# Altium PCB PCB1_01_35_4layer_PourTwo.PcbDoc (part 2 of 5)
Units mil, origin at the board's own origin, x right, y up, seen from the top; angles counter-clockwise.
Board outline 1043.31 x 669.29 mil, 4 copper layers (Top Layer, Layer 1, Layer 2, Bottom Layer), stack 23.756 mil thick; 0 components, 1 nets, 8 pads, 85 vias.

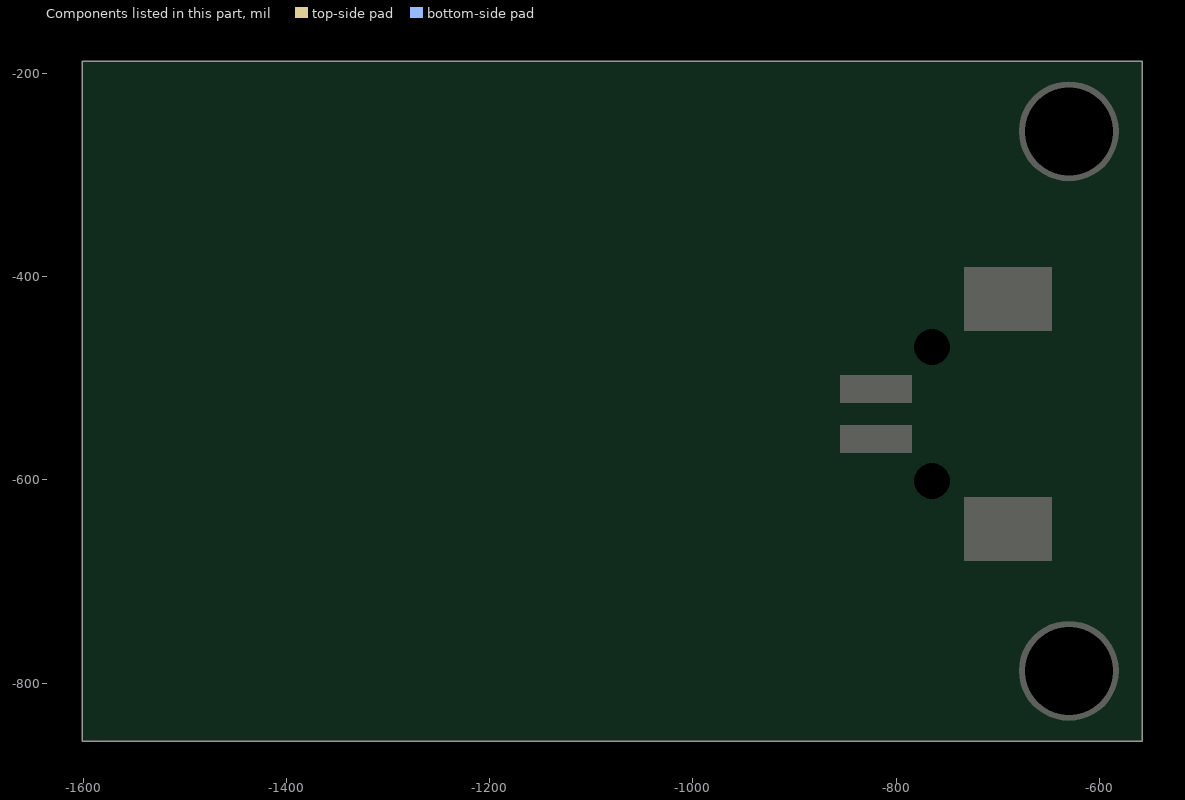
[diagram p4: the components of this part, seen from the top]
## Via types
v1: diameter 19.68, hole 11.81, Top Layer to Bottom Layer, tented both sides, 70 vias
v2: diameter 39.37, hole 19.68, Top Layer to Bottom Layer, 9 vias
v3: diameter 19.68, hole 11.81, Top Layer to Bottom Layer, 6 vias

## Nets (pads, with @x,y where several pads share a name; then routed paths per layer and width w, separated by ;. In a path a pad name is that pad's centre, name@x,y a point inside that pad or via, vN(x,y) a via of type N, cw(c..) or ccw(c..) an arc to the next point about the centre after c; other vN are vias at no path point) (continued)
copper on no net: | length 155578.5
  Top Layer w3.94: v3(-1265,-540) -1267.14,-537.86 -1277.26,-537.86 -1282.59,-532.53 -1296.93,-518.19 cw(c-1256.96,-523.28) -1294.61,-508.93 cw(c-1253.35,-524.64) -1290.23,-500.37 cw(c-1251.13,-526.07) -1284.09,-492.87 cw(c-1251.02,-526.13) -1276.51,-486.75 cw(c-1252.19,-524.27) -1267.78,-482.37 cw(c-1253.24,-521.43) -1258.21,-480.05 cw(c-1253.23,-522.64) -1248.3,-480.04 cw(c-1253.65,-526.46) -1238.57,-482.23 cw(c-1254.28,-528.41) -1229.43,-486.44 cw(c-1253.91,-527.86) -1221.33,-492.45 cw(c-1252.04,-525.86) -1214.69,-500.1 cw(c-1250.8,-524.81) -1207.42,-519.1 cw(c-1256.17,-525.78) -1207.1,-529.44 cw(c-1256.93,-525.82) -1212.86,-549.37 cw(c-1253.35,-527.65) -1218.84,-557.99 cw(c-1252.02,-528.72) -1226.74,-565.03 cw(c-1254.37,-525.34) -1236.08,-570.1 cw(c-1255.6,-522.41) -1246.37,-573.11 cw(c-1255.74,-521.9) -1257.1,-573.94 cw(c-1255.82,-524.09) -1267.8,-572.5 cw(c-1256.65,-527.38) -1277.97,-568.68 cw(c-1256.38,-527.19) -1287.01,-562.53 cw(c-1253.58,-523.93) -1294.51,-554.47 cw(c-1251.52,-522.34) -1300.19,-544.96 cw(c-1251.86,-522.45) -1303.81,-534.44 cw(c-1254.63,-523.07) -1305.1,-523.37 cw(c-1258.03,-523.09) -1303.83,-512.2 cw(c-1255.62,-523.78) -1299.96,-501.6 cw(c-1251.91,-525.6) -1293.83,-492.02 cw(c-1250.76,-526.42) -1276.23,-477.54 cw(c-1252.73,-522.76) -1265.48,-473.42 cw(c-1253.45,-520.19) -1253.97,-471.9 cw(c-1253.43,-524.34) -1242.38,-473.07 cw(c-1254.18,-528.01) -1231.22,-476.72 cw(c-1254.55,-528.93) -1221,-482.62 cw(c-1253.29,-527.26) -1212.22,-490.54 cw(c-1250.51,-524.79) -1205.38,-500.25 cw(c-1249.89,-524.29) -1200.98,-511.37 cw(c-1254.44,-525.51) -1199.18,-523.26 cw(c-1257.61,-525.68) -1199.94,-535.34 cw(c-1257.66,-525.72) -1203.17,-547.06 cw(c-1255.01,-526.79) -1208.82,-557.85 cw(c-1251.8,-528.95) -1216.81,-567.14 cw(c-1252.8,-527.63) -1226.81,-574.33 cw(c-1255.09,-523.58) -1238.21,-579.17 cw(c-1255.83,-521.27) -1250.45,-581.55 cw(c-1255.79,-522.21) -1262.96,-581.36 cw(c-1256.24,-525.69) -1275.15,-578.48 cw(c-1256.68,-527.57) -1296.14,-564.66 cw(c-1252.1,-522.82) -1303.91,-554.53 cw(c-1251.52,-522.32) -1312.48,-530.47 cw(c-1256.57,-523.09) -1312.7,-517.57 cw(c-1258.54,-523.01) -1309.87,-504.9 cw(c-1253.84,-524.66) -1304.21,-493.15 cw(c-1250.61,-526.63) -1296.13,-482.8 cw(c-1250.2,-526.96) -1286.06,-474.29 cw(c-1251.74,-524.63) -1274.4,-468.08 cw(c-1253.31,-520.68) -1261.59,-464.61 cw(c-1253.42,-521.25) -1248.25,-464.26 cw(c-1253.85,-526.37) -1235.1,-466.89 cw(c-1254.72,-529.28) -1222.71,-472.25 cw(c-1254.41,-528.82) -1211.66,-480.07 cw(c-1252.04,-526.16) -1202.51,-490.07 cw(c-1248.66,-523.69) -1195.85,-501.99 cw(c-1251.66,-524.79) -1192.14,-515.17 cw(c-1256.48,-525.61) -1191.39,-528.93 cw(c-1258.01,-525.64) -1198.42,-555.61 cw(c-1253.34,-527.91) -1206.05,-567.25 cw(c-1250.89,-529.85) -1216.26,-576.86 cw(c-1253.85,-525.8) -1228.44,-583.89 cw(c-1255.65,-521.78) -1241.92,-588.18 cw(c-1255.92,-520.74) -1256.07,-589.62 cw(c-1255.97,-523.38) -1270.21,-588.07 cw(c-1256.96,-527.83) -1283.72,-583.41 cw(c-1257.13,-528.59) -1295.82,-575.65 cw(c-1253.61,-524.27) -1305.91,-565.34 cw(c-1250.73,-521.95) -1313.66,-553.05 cw(c-1250.83,-521.94) -1318.73,-539.4 cw(c-1254.26,-522.78) -1320.8,-524.96 cw(c-1258.97,-522.93) -1319.54,-510.34 cw(c-1256.87,-523.55) -1314.87,-496.38 cw(c-1251.93,-525.83) -1307.2,-483.72 cw(c-1249.69,-527.47) -1297.02,-472.86 cw(c-1250.47,-526.49) -1284.79,-464.32 cw(c-1252.51,-522.73) -1270.99,-458.61 cw(c-1253.37,-520.73) -1241.1,-457.34 cw(c-1254.47,-528.4) -1226.56,-461.69 cw(c-1254.6,-529.11) -1201.58,-478.91 cw(c-1250.16,-524.75) -1192.42,-491.17 cw(c-1248.38,-523.54) -1186.35,-505.33 cw(c-1254,-525.2) -1183.64,-520.54 cw(c-1258.35,-525.54) -1184.22,-536.07 cw(c-1258.83,-525.53) -1187.99,-551.21 cw(c-1255.63,-526.74) -1194.86,-565.23 cw(c-1251.33,-529.48) -1204.75,-577.4 cw(c-1251.79,-528.69) -1217.27,-586.95 cw(c-1254.85,-523.58) -1231.67,-593.52 cw(c-1255.99,-520.32) -1247.21,-596.95 cw(c-1255.96,-521.1) -1263.16,-597.11 cw(c-1256.4,-525.38) -1278.79,-593.86 cw(c-1257.93,-530.08) -1293.35,-587.08 cw(c-1255.74,-526.81) -1305.95,-577.06 cw(c-1251.78,-522.79) -1316.14,-564.47 cw(c-1250.52,-521.81) -1327.8,-534.25 cw(c-1256.67,-522.9) -1328.53,-517.94 cw(c-1260.19,-522.75) -1325.42,-501.81 cw(c-1254.58,-524.57) -1318.67,-486.78 cw(c-1250.21,-527.09) -1308.82,-473.46 cw(c-1249.35,-527.8) -1296.4,-462.41 cw(c-1251.18,-525.17) -1281.93,-454.19 cw(c-1253.32,-520.19) -1265.94,-449.37 cw(c-1253.64,-519.61) -1249.18,-448.44 cw(c-1254.02,-526.02) -1232.59,-451.3 cw(c-1255.11,-530.05) -1216.87,-457.62 cw(c-1254.96,-529.88) -1202.75,-467.05 cw(c-1252.21,-526.65) -1190.95,-479.27 cw(c-1247.83,-523.27) -1182.18,-493.93 cw(c-1250.45,-524.22) -1177.07,-510.28 cw(c-1256.56,-525.42) -1175.67,-527.44 cw(c-1259.14,-525.47) -1183.57,-560.97 cw(c-1253.55,-528.02) -1192.67,-575.73 cw(c-1251.51,-529.18) -1219.91,-597.23 cw(c-1255.65,-521.33) -1236.52,-603.01 cw(c-1255.97,-520.77) -1271.66,-603.81 cw(c-1257.2,-528.02) -1288.56,-598.52 cw(c-1257.12,-528.46) -1303.87,-589.37 cw(c-1253.5,-523.69) -1316.82,-577.01 cw(c-1251.82,-522.11) -1333.64,-545.42 cw(c-1257.54,-523.82) -1336.56,-527.6 cw(c-1257.16,-524.04) -1335.3,-509.51 cw(c-1251.66,-525.02) -1330.08,-492.06 cw(c-1250.73,-525.22) -1309.27,-462.22 cw(c-1255.41,-520.37) -1294.43,-451.38 cw(c-1254.18,-522.94) -1277.46,-444.21 cw(c-1252.68,-527.83) -1259.25,-440.86 cw(c-1252.54,-528.84) -1240.68,-441.41 cw(c-1252.03,-525.45) -1222.63,-445.91 cw(c-1251.24,-522.58) -1191.66,-466.47 cw(c-1256.32,-527.92) -1180.21,-481.4 cw(c-1256.29,-527.98) -1172.11,-498.45 cw(c-1252.31,-526.64) -1167.87,-516.87 cw(c-1248.57,-526.1) -1167.93,-535.85 cw(c-1254.56,-525.38) -1172.26,-554.39 cw(c-1258.09,-524.2) -1180.47,-571.67 cw(c-1257.26,-524.78) -1192.15,-586.87 cw(c-1253.77,-528.17) -1206.88,-599.19 cw(c-1252.7,-529.4) -1224.11,-607.84 cw(c-1254.87,-523.56) -1242.9,-612.48 cw(c-1255.29,-521.49) -1281.46,-609.51 cw(c-1257.11,-527.94) -1299.39,-601.82 cw(c-1256.38,-527.17) -1315.14,-590.18 cw(c-1252.4,-522.83) -1328.01,-575.32 cw(c-1252.01,-522.31) -1343.14,-539.1 cw(c-1259.26,-523.81) -1344.4,-519.31 cw(c-1255.65,-524.18) -1341.1,-499.71 cw(c-1250.51,-525.6) -1333.61,-481.2 cw(c-1249.76,-525.92) -1322.38,-464.62 cw(c-1252.71,-523.36) -1307.84,-450.81 cw(c-1254.61,-521.4) -1271.24,-434.56 cw(c-1252.71,-528.95) -1251.04,-432.78 cw(c-1252.64,-528.68) -1230.87,-435.27 cw(c-1251.52,-524.1) -1211.69,-442.05 cw(c-1250.08,-520.82) -1194.49,-453.09 cw(c-1254.24,-525.9) -1180.16,-467.73 cw(c-1257.15,-528.28) -1169.21,-485.15 cw(c-1255.89,-527.74) -1162.15,-504.52 cw(c-1250.65,-526.48) -1159.47,-525 cw(c-1249.56,-526.22) -1161.58,-545.63 cw(c-1256.01,-524.84) -1168.21,-565.34 cw(c-1257.77,-524.21) -1193.12,-598.6 cw(c-1252.8,-529.75) -1210.44,-610.41 cw(c-1253.4,-528.05) -1230.06,-617.97 cw(c-1255,-522.12) -1250.94,-621.07 cw(c-1255.14,-520.4) -1272.08,-619.73 cw(c-1255.79,-523.81) -1292.47,-613.92 cw(c-1258.07,-529.4) -1311.1,-603.66 cw(c-1255.35,-525.87) -1326.95,-589.38 cw(c-1251.27,-522.17) -1339.4,-571.95 cw(c-1250.8,-521.82) -1347.94,-552.25 cw(c-1255.03,-523.08) -1352.08,-531.16 cw(c-1257.35,-523.68) -1345.7,-488.7 cw(c-1249.6,-526.23) -1335.72,-469.41 cw(c-1250.04,-525.84) -1321.88,-452.61 cw(c-1253.67,-522.07) -1304.71,-439.17 cw(c-1255.54,-519.38) -1284.86,-429.98 cw(c-1253.32,-526.08) -1263.39,-425.44 cw(c-1252.87,-529.81) -1241.36,-425.54 cw(c-1252.61,-528.08) -1219.82,-430.28 cw(c-1250.68,-522.48) -1199.79,-439.64 cw(c-1250.68,-521.94) -1182.38,-453.39 cw(c-1255.53,-526.88) -1168.39,-470.68 cw(c-1256.73,-527.88) -1152.66,-512.24 cw(c-1248.67,-526.53) -1151.94,-534.64 cw(c-1251.25,-526.05) -1156.39,-556.67 cw(c-1257.33,-524.15) -1165.55,-577.29 cw(c-1258.7,-523.45) -1178.87,-595.58 cw(c-1255.8,-526.15) -1195.79,-610.63 cw(c-1252.12,-531.33) -1215.73,-621.54 cw(c-1253.98,-526.36) -1237.68,-627.63 cw(c-1254.94,-520.79) -1260.51,-628.87 cw(c-1255,-520.48) -1283.15,-625.3 cw(c-1256.34,-525.23) -1304.52,-616.94 cw(c-1258.68,-529.88) -1323.5,-603.91 cw(c-1254.05,-524.62) -1339.1,-586.89 cw(c-1250.26,-521.75) -1350.76,-566.86 cw(c-1251.14,-522.06) -1357.97,-544.79 cw(c-1256.8,-523.21) -1360.24,-521.66 cw(c-1259.63,-523.39) -1357.13,-498.53 cw(c-1252.35,-525.21) -1348.94,-476.62 cw(c-1249.62,-526.41) -1319.69,-440.19 cw(c-1254.68,-520.35) -1299.82,-427.54 cw(c-1254.82,-520.74) -1277.52,-419.76 cw(c-1253.19,-527.75) -1253.97,-417.06 cw(c-1252.96,-528.94) -1207.64,-426.64 cw(c-1249.51,-520.74) -1187.1,-438.8 cw(c-1251.84,-523.38) -1169.86,-455.38 cw(c-1256.85,-527.63) -1156.57,-475.38 cw(c-1257.97,-528.31) -1147.74,-497.78 cw(c-1253.64,-527.18) -1143.87,-521.56 ; -1143.92,-649.83 ccw(c-1254.27,-527.48) -1119.72,-622.57 ccw(c-1259.21,-523.85) -1101.97,-590.77 ccw(c-1257.09,-524.63) -1091.4,-555.99 ccw(c-1247.91,-526.29) -1088.74,-519.81 ccw(c-1252.03,-526.77) -1094.28,-484.03 ccw(c-1258.09,-528.3) -1107.38,-450.31 ccw(c-1256.34,-527.26) -1127.31,-420.2 ccw(c-1249.3,-521.33) -1153.32,-395.25 ccw(c-1251.27,-524.44) -1184.21,-376.84 ccw(c-1254,-530.2) -1218.31,-365.53 ccw(c-1253.73,-528.4) -1253.98,-361.72 ccw(c-1253.83,-519.14) -1289.54,-365.83 ccw(c-1253.16,-519.96) -1323.12,-377.88 ccw(c-1249.17,-528.27) -1353.26,-396.93 ccw(c-1248.11,-529.79) -1378.72,-421.85 ccw(c-1253.51,-525.47) -1398.24,-451.52 ccw(c-1263.14,-520.54) -1410.57,-484.77 ccw(c-1255.65,-522.17) -1415,-519.87 ccw(c-1247.68,-522.38) -1411.79,-555.09 ccw(c-1247.71,-522.51) -1401.29,-588.81 ccw(c-1255.33,-525.91) -1383.87,-619.4 ccw(c-1262.38,-530.83) -1359.97,-645.2 ccw(c-1256.01,-523.32) -1330.95,-664.9 ccw(c-1252.86,-517.61) -1298.4,-677.98 ccw(c-1253.28,-519.52) -1263.91,-683.94 ccw(c-1253.81,-529.03) -1229.05,-682.28 ccw(c-1253.42,-533.71) -1195.54,-672.69 ccw(c-1258.72,-521.67) -1138.8,-633.11 ccw(c-1257.18,-522.66) -1117.99,-605.36 ccw(c-1248.17,-527.93) -1103.81,-573.79 ccw(c-1248.34,-528.35) -1097.28,-539.87 ccw(c-1260,-527.61) -1106.61,-471.92 ccw(c-1255.92,-525.9) -1121.73,-441.04 ccw(c-1246.77,-520.05) -1143.31,-414.35 ccw(c-1249.74,-523.56) -1170.34,-393.37 ccw(c-1254.28,-530.84) -1201.27,-378.74 ccw(c-1254.83,-532.06) -1234.54,-370.93 ccw(c-1254.06,-525.1) -1268.6,-370.38 ccw(c-1254.96,-515.06) -1301.86,-377.51 ccw(c-1252.24,-522.63) -1332.55,-391.97 ccw(c-1248.48,-528.93) -1359.43,-412.67 ccw(c-1248.92,-528.64) -1381.34,-438.49 ccw(c-1255.85,-524.03) -1397.13,-468.33 ccw(c-1262.74,-521.1) -1405.71,-500.93 ccw(c-1253.16,-522.45) -1406.74,-534.55 ccw(c-1247.28,-522.09) -1400.61,-567.61 ccw(c-1249.47,-522.86) -1387.72,-598.59 ccw(c-1257.67,-527.44) -1368.45,-625.94 ccw(c-1260.5,-529.45) -1343.46,-648.11 ccw(c-1253.62,-519.21) -1282.3,-673.69 ccw(c-1253.77,-521.58) -1249.16,-676.27 ccw(c-1253.4,-531.77) -1216.34,-671.51 ccw(c-1254.09,-530.79) -1185.57,-659.36 ccw(c-1258.25,-522.83) -1158.22,-640.8 ccw(c-1259.85,-520.78) -1135.39,-616.93 ccw(c-1255.33,-524.14) -1118.19,-588.85 ccw(c-1245.92,-528.54) -1107.71,-557.7 ccw(c-1251.18,-527.71) -1104.63,-525.07 ccw(c-1259.13,-527.77) -1108.68,-492.55 ccw(c-1259.98,-527.85) -1119.43,-461.65 ccw(c-1249.28,-522.09) -1159.32,-410.63 ccw(c-1251.38,-525.64) -1186.76,-393.25 ccw(c-1254.4,-531.62) -1217.27,-382.15 ccw(c-1254.29,-530.71) -1249.38,-377.68 ccw(c-1254.11,-522.44) -1281.58,-380.24 ccw(c-1255.08,-516.16) -1312.32,-390.06 ccw(c-1249.65,-527.35) -1363.58,-428.37 ccw(c-1250.18,-527.34) -1381.99,-454.67 ccw(c-1258.31,-522.95) -1394.18,-484.26 ccw(c-1260.39,-521.95) -1399.25,-515.81 ccw(c-1248.89,-522.27) -1388.57,-578.32 ccw(c-1251.45,-523.56) -1373.67,-606.4 ccw(c-1259.63,-529.17) -1352.98,-630.44 ccw(c-1258.48,-527.37) -1327.39,-649.04 ccw(c-1254.29,-520.12) -1298.39,-661.61 ccw(c-1253.57,-518.16) -1267.43,-667.81 ccw(c-1254,-523.9) -1235.95,-667.31 ccw(c-1252.75,-533.67) -1205.45,-659.78 ccw(c-1255.03,-528.22) -1177.55,-645.53 ccw(c-1259,-522.06) -1153.38,-625.61 ccw(c-1259.21,-521.7) -1133.94,-601.12 ccw(c-1248.9,-527.51) -1113.26,-542.8 ccw(c-1253.62,-527.47) -1113.3,-511.77 ccw(c-1259.69,-528.06) -1119.96,-481.47 ccw(c-1258.51,-527.55) -1132.79,-453.29 ccw(c-1251.51,-523.33) -1151.35,-428.63 ccw(c-1247.52,-519.94) -1175.01,-408.9 ccw(c-1253.73,-529.93) -1232.14,-387.18 ccw(c-1253.89,-528.93) -1262.76,-385.79 ccw(c-1254.52,-519.9) -1292.85,-391.13 ccw(c-1254.48,-518.67) -1320.86,-403.2 ccw(c-1249.03,-527.82) -1365.78,-443.79 ccw(c-1251.84,-526.07) -1380.78,-470.16 ccw(c-1260.64,-522.3) -1389.54,-499.13 ccw(c-1257.67,-522.5) -1391.42,-529.26 ccw(c-1249.9,-522.18) -1386.72,-559.05 ccw(c-1248.34,-521.87) -1375.89,-587.16 ccw(c-1253.48,-524.6) -1359.38,-612.25 ccw(c-1260.6,-530.49) -1337.71,-632.94 ccw(c-1256.93,-525.33) -1311.96,-648.12 ccw(c-1254.1,-519.22) -1283.57,-657.4 ccw(c-1254,-519.27) -1253.92,-660.53 ccw(c-1253.92,-526.31) -1224.39,-657.24 ccw(c-1252.42,-533.55) -1196.42,-647.35 ccw(c-1256.07,-526.19) -1171.47,-631.45 ccw(c-1259.45,-521.85) -1150.48,-610.61 ccw(c-1258.13,-522.79) -1134.36,-585.89 ccw(c-1250.93,-526.38) -1124.01,-558.36 ccw(c-1247.01,-527.68) -1120.25,-529.24 ccw(c-1258.04,-527.77) -1131.95,-472.19 ccw(c-1256.79,-526.92) -1146.47,-446.86 ccw(c-1249.69,-521.69) -1166.14,-425.39 ccw(c-1249.31,-521.82) -1190.16,-409.05 ccw(c-1253.75,-530.56) -1245.72,-393.65 ccw(c-1253.72,-526.87) -1274.57,-395.05 ccw(c-1255.19,-517.81) -1302.33,-402.82 ccw(c-1253.53,-521.11) -1327.5,-416.69 ccw(c-1249.44,-527.01) -1349.04,-435.67 ccw(c-1248.66,-527.86) -1366.11,-458.72 ccw(c-1253.76,-524.95) -1377.84,-484.77 ccw(c-1261.9,-522.29) -1383.38,-512.75 ccw(c-1255.3,-522.69) -1382.43,-541.17 ccw(c-1249.21,-521.89) -1375.41,-568.71 ccw(c-1249.55,-522.12) -1362.81,-594.12 ccw(c-1255.39,-525.93) -1345.1,-616.16 ccw(c-1260.04,-530.36) -1322.88,-633.55 ccw(c-1255.87,-523.52) -1297.39,-645.47 ccw(c-1254.2,-518.88) -1269.97,-651.71 ccw(c-1254.33,-520.79) -1241.91,-652.05 ccw(c-1253.52,-528.62) -1214.54,-646.31 ccw(c-1252.86,-531.63) -1189.27,-634.47 ccw(c-1258.42,-523) -1149.44,-596.01 ccw(c-1256.67,-523.88) -1136.52,-571.46 ccw(c-1248.7,-526.98) -1129.33,-544.74 ccw(c-1249.51,-527.21) -1128.48,-517.16 ccw(c-1256.94,-527.77) -1133.67,-490.09 ccw(c-1259.06,-528.32) -1144.42,-464.75 ccw(c-1255.01,-525.97) -1160.23,-442.33 ccw(c-1248.48,-520.18) -1180.61,-424.05 ccw(c-1250.76,-523.8) -1204.54,-410.95 ccw(c-1253.32,-529.88) -1230.73,-403.33 ccw(c-1253.54,-530.58) -1257.88,-401.38 ccw(c-1254.43,-520.47) -1309.96,-415.06 ccw(c-1252.49,-523.06) -1332.24,-430.29 ccw(c-1248.92,-527.33) -1350.74,-449.92 ccw(c-1249.57,-526.96) -1364.69,-472.94 ccw(c-1255.82,-524.1) -1373.32,-498.33 ccw(c-1261.08,-522.75) -1375.92,-524.97 ccw(c-1253.38,-522.61) -1372.5,-551.44 ccw(c-1249.1,-521.66) -1363.56,-576.58 ccw(c-1251.01,-522.68) -1349.57,-599.21 ccw(c-1257.04,-527.44) -1331.05,-618.19 ccw(c-1258.59,-528.83) -1308.72,-632.38 ccw(c-1254.61,-520.23) -1257.71,-644.71 ccw(c-1254.46,-522.58) -1231.5,-642.58 ccw(c-1252.86,-530.67) -1206.48,-634.73 ccw(c-1253.78,-529.37) -1183.99,-621.39 ccw(c-1257.9,-523.84) -1164.98,-603.49 ccw(c-1259.16,-522.65) -1150.17,-582.03 ccw(c-1254.95,-524.85) -1140.28,-558 ccw(c-1247.06,-527.11) -1136.03,-532.43 ccw(c-1251.79,-527.07) -1137.72,-506.64 ccw(c-1257.73,-528.07) -1144.92,-481.85 ccw(c-1258.08,-528.12) -1157.13,-459.16 ccw(c-1250.29,-522.17) -1194.51,-424.51 ccw(c-1251.75,-525.57) -1217.98,-414.44 ccw(c-1253.28,-530.35) -1243.05,-409.62 ccw(c-1253.28,-529.3) -1268.5,-410.15 ccw(c-1254.2,-522.62) -1293.16,-416.15 ccw(c-1255.52,-518.37) -1315.74,-427.6 ccw(c-1250.04,-526.23) -1350.67,-463.63 ccw(c-1250.83,-526.04) -1361.64,-486.27 ccw(c-1257.87,-523.57) -1367.39,-510.67 ccw(c-1258.95,-523.12) -1367.38,-535.68 ccw(c-1250.35,-521.99) -1351.37,-582.63 ccw(c-1252.56,-523.53) -1336.4,-602.45 ccw(c-1258.28,-528.98) -1317.45,-618.42 ccw(c-1257.26,-526.94) -1295.42,-629.58 ccw(c-1255.01,-521.03) -1271.52,-635.67 ccw(c-1254.74,-519.74) -1246.91,-636.62 ccw(c-1254.34,-524.49) -1222.76,-632.33 ccw(c-1252.2,-531.82) -1200.23,-622.76 ccw(c-1254.81,-527.52) -1180.55,-608.35 ccw(c-1258.47,-523.45) -1164.43,-590.07 ccw(c-1258.42,-523.38) -1152.53,-568.86 ccw(c-1249.59,-526.65) -1143.88,-521.56 ; -1143.92,-649.82 cw(c-1250.98,-530.7) -1173.69,-670.98 cw(c-1255.6,-522.46) -1207.45,-685.09 cw(c-1256.42,-520.13) -1243.5,-691.72 cw(c-1256.07,-526.12) -1280.17,-690.44 cw(c-1256.54,-531.16) -1315.68,-680.93 cw(c-1253.1,-522.25) -1348.28,-663.8 cw(c-1251.7,-519.95) -1376.56,-640.08 cw(c-1256,-523.94) -1399.09,-610.82 cw(c-1260.57,-527) -1414.5,-577.18 cw(c-1251.44,-523.96) -1422.13,-540.9 cw(c-1250.97,-523.53) -1413.63,-467.51 cw(c-1259.9,-521.06) -1397.43,-433.97 cw(c-1251.68,-526.2) -1374.19,-404.78 cw(c-1250.85,-526.51) -1311.81,-364.29 cw(c-1254.73,-517.71) -1275.41,-355.33 cw(c-1253.45,-527.36) -1237.86,-354.63 cw(c-1253.19,-528.51) -1166.45,-377.04 cw(c-1248.7,-519.64) -1136.14,-399.51 cw(c-1255.34,-526.77) -1111.52,-428.19 cw(c-1256.33,-527.88) -1083.09,-497.95 cw(c-1246.3,-525.66) -1081.07,-535.86 cw(c-1256.03,-525.08) -1087.51,-573.35 cw(c-1257.82,-524.93) -1123.37,-640.14 cw(c-1249.51,-531.46) -1151.47,-666.04 cw(c-1255.24,-523.6) -1184.67,-685.08 cw(c-1256.38,-521.83) -1259.48,-700.11 cw(c-1256.15,-532.66) -1297.58,-694.94 cw(c-1253.75,-523.3) -1333.64,-681.41 cw(c-1252.96,-521) -1393.27,-633.04 cw(c-1257.48,-525.8) -1426.34,-563.55 cw(c-1250.1,-523.24) -1427.08,-486.29 cw(c-1257.01,-522.7) -1394.41,-416.07 cw(c-1250.06,-526.97) -1334.98,-365.96 cw(c-1254.17,-520.97) -1259.59,-346.24 cw(c-1253.03,-529.4) -1182.62,-360.19 cw(c-1250.85,-522.11) -1118.99,-405.98 cw(c-1256.88,-528.57) -1080.44,-474.61 cw(c-1249.54,-525.55) -1075.13,-553.31 cw(c-1258.69,-524.96) -1103.62,-627.19 cw(c-1251.44,-528.92) -1161.22,-681.78 cw(c-1256.97,-521.21) -1236.77,-707.07 cw(c-1255.44,-533.1) -1276.91,-706.75 cw(c-1254.25,-524.75) -1316.02,-697.44 cw(c-1252.88,-520.17) -1384.07,-655.08 cw(c-1261.12,-528.95) -1409.56,-623.76 cw(c-1254.17,-524.73) -1427.42,-587.47 cw(c-1249.42,-522.76) -1438.21,-507.56 cw(c-1261.47,-521.99) -1430.29,-467.71 cw(c-1254.11,-524.57) -1413.62,-430.6 cw(c-1249.27,-527.16) -1358.59,-371.01 cw(c-1256.34,-517.37) -1322.63,-351.59 cw(c-1253.8,-524.37) -1283.17,-340.72 cw(c-1252.61,-530.98) -1242.21,-338.56 cw(c-1252.32,-528.04) -1201.69,-345.17 cw(c-1249.61,-518.44) -1163.58,-360.59 cw(c-1253.22,-524.51) -1129.86,-384.2 cw(c-1257.72,-529.82) -1101.93,-414.57 cw(c-1255.44,-528.3) -1081.08,-450.21 cw(c-1246.26,-524.25) -1068.58,-489.63 cw(c-1252.85,-525.24) -1065.26,-530.91 cw(c-1260.05,-525.15) -1070.9,-572.02 cw(c-1257.63,-525.88) -1085.16,-611.04 cw(c-1248.63,-530.4) -1107.69,-646 cw(c-1253.25,-526.2) -1137.55,-675.03 cw(c-1257.91,-520.4) -1173.04,-697.02 cw(c-1257.04,-522.54) -1212.42,-710.98 cw(c-1254.78,-532.37) -1253.96,-715.93 cw(c-1254.46,-526.59) -1295.6,-711.41 cw(c-1252.92,-519.06) -1335.39,-698 cw(c-1253.91,-520.9) -1371.45,-676.42 cw(c-1260.06,-528.89) -1401.92,-647.41 cw(c-1255.74,-525.77) -1425.12,-612.24 cw(c-1248.75,-522.06) -1440.23,-572.81 cw(c-1250.58,-522.41) -1446.62,-531.03 cw(c-1260.63,-522.76) -1443.68,-488.81 cw(c-1255.97,-524.03) -1431.29,-448.29 cw(c-1248.43,-527.15) -1410.42,-411.31 cw(c-1249.67,-526.09) -1382.13,-379.57 cw(c-1256.33,-518.6) -1347.54,-354.78 cw(c-1254.6,-522.56) -1308.2,-338.4 cw(c-1252.13,-530.59) -1266.16,-330.88 cw(c-1252.09,-529.19) -1223.43,-332.46 cw(c-1250.56,-519.34) -1182.05,-343.37 cw(c-1252.34,-522.69) -1144.14,-363.35 cw(c-1257.09,-529.91) -1111.36,-391.11 cw(c-1256.15,-529.21) -1085.2,-425.23 cw(c-1247.64,-524.14) -1067.12,-464.29 cw(c-1250.84,-524.73) -1058.3,-506.48 cw(c-1259.67,-525.69) -1058.81,-549.67 cw(c-1258.78,-525.94) -1068.49,-591.81 cw(c-1249.52,-529.25) -1087.16,-630.86 cw(c-1251.53,-527.43) -1114.19,-664.73 cw(c-1258.06,-521.07) -1147.98,-692.01 cw(c-1257.82,-521.72) -1186.84,-711.52 cw(c-1254.5,-530.88) -1229.06,-722.09 cw(c-1254.29,-528.74) -1272.64,-722.87 cw(c-1253.53,-519.42) -1315.43,-714.16 cw(c-1253.8,-519.79) -1355.46,-696.55 cw(c-1258.7,-528.1) -1390.71,-670.62 cw(c-1257.31,-527.33) -1419.24,-637.36 cw(c-1249.45,-521.84) -1439.92,-598.62 cw(c-1249.67,-521.77) -1451.92,-556.32 cw(c-1259.09,-523.27) -1454.43,-512.39 cw(c-1258.21,-523.83) -1446.95,-468.96 cw(c-1248.75,-526.45) -1430.18,-428.11 cw(c-1248.62,-526.36) -1405.1,-391.71 cw(c-1255.69,-520.13) -1372.67,-361.6 cw(c-1255.92,-520.67) -1334.24,-339.56 cw(c-1251.82,-529.85) -1291.84,-326.38 cw(c-1251.61,-530.15) -1247.56,-322.49 cw(c-1251.32,-520.84) -1203.46,-328.31 cw(c-1251.74,-520.42) -1161.75,-343.96 cw(c-1256.3,-529.64) -1124.37,-368.36 cw(c-1256.56,-530.19) -1092.97,-400.17 cw(c-1249.3,-524.56) -1069.22,-438.07 cw(c-1248.68,-523.71) -1054.6,-480.41 cw(c-1258.91,-526.11) -1049.56,-525 cw(c-1259.76,-526.26) -1054.09,-569.71 cw(c-1250.93,-528.25) -1068.22,-612.4 cw(c-1249.32,-528.44) -1091.65,-650.86 cw(c-1257.87,-521.96) -1122.97,-683.35 cw(c-1258.69,-521.2) -1160.52,-708.48 cw(c-1254.66,-529.15) -1202.64,-724.89 cw(c-1253.63,-531.12) -1247.45,-731.39 cw(c-1254.09,-520.18) -1292.68,-727.94 cw(c-1253.98,-518.8) -1336.2,-714.96 cw(c-1257.48,-526.85) -1375.91,-692.85 cw(c-1258.72,-529.39) -1409.67,-662.31 cw(c-1250.43,-521.94) -1435.98,-625.06 cw(c-1249.06,-521) -1453.8,-583.02 cw(c-1257.35,-523.39) -1462.13,-538.09 cw(c-1260.71,-524.09) -1460.11,-492.38 cw(c-1249.49,-525.76) -1448.11,-448.13 cw(c-1247.65,-526.32) -1426.96,-407.39 cw(c-1254.65,-521.53) -1397.49,-372.15 cw(c-1257.74,-518.93) -1360.79,-344.41 cw(c-1251.79,-528.8) -1318.83,-325.36 cw(c-1250.95,-530.83) -1273.71,-315.64 cw(c-1251.7,-522.54) -1227.54,-315.88 cw(c-1251.58,-517.91) -1182.54,-326.53 cw(c-1255.45,-528.94) -1140.9,-346.83 cw(c-1256.64,-531.11) -1104.46,-375.56 cw(c-1250.84,-525.37) -1075.06,-411.47 cw(c-1246.68,-522.2) -1054.47,-453.15 cw(c-1257.79,-526.3) -1043.52,-498.41 cw(c-1260.49,-526.81) -1042.43,-545.03 cw(c-1252.54,-527.6) -1051.41,-590.82 cw(c-1246.89,-528.99) -1070.49,-633.48 cw(c-1257.25,-522.96) -1098.53,-670.95 cw(c-1259.56,-521.01) -1133.95,-701.66 cw(c-1255.21,-527.51) -1175.16,-724.05 cw(c-1252.49,-533.28) -1220.42,-736.61 cw(c-1254.45,-521.35) -1267.41,-738.9 cw(c-1254.41,-518.04) -1313.89,-731.13 cw(c-1256.59,-525.36) -1357.63,-713.56 cw(c-1259.6,-531.63) -1396.36,-686.56 cw(c-1251.59,-522.44) -1428.24,-651.63 cw(c-1251.53,-521.79) -1466.41,-565.52 cw(c-1262.93,-524.86) -1470.32,-518.22 cw(c-1250.68,-525.19) -1463.69,-471.16 cw(c-1249.76,-524.93) -1421.44,-386.43 cw(c-1259.72,-517.8) -1387.33,-353.1 cw(c-1252.14,-527.48) -1346.63,-328.09 cw(c-1251.19,-528.38) -1253.95,-306.53 cw(c-1252.01,-515.75) -1206.28,-311.58 cw(c-1254.66,-527.78) -1160.84,-327.08 cw(c-1254.93,-529.44) -1084.77,-385.05 cw(c-1245.39,-520.52) -1058.14,-425.2 cw(c-1256.35,-526.13) -1041.03,-470.31 cw(c-1258.19,-527.07) -1037.21,-566.36 cw(c-1244.89,-528.84) -1051.22,-612.71 cw(c-1256.15,-523.98) -1075.21,-654.85 cw(c-1258.37,-522.91) -1147.14,-719.34 cw(c-1251.12,-534.6) -1192,-738.18 cw(c-1254.51,-522.9) -1240,-746.6 cw(c-1255.12,-520.09) -1336.02,-732.21 cw(c-1256.96,-528.26) -1416.62,-677.77 cw(c-1250.75,-520.9) -1466.96,-594.19 cw(c-1258.65,-524.78) -1476.45,-496.91 cw(c-1248.6,-524.93) -1443.97,-404.39 cw(c-1256.95,-521.04) -1374.73,-334.74 cw(c-1250.45,-529.25) -1282.28,-300.63 cw(c-1252.78,-519.91) -1184,-309.61 cw(c-1255.1,-530.55) -1098.38,-359.36 cw(c-1249.06,-522.54) -1042.38,-441.21 cw(c-1259.12,-527.66) -1026.07,-539.36 cw(c-1248.71,-527.29) -1053.56,-635.14 cw(c-1259.4,-522.6) -1119.12,-710.64 cw(c-1250.09,-534.56) -1162.7,-735.85 cw(c-1254.15,-524.75) -1210.88,-750.7 cw(c-1255.56,-519.13) -1311.32,-748.29 cw(c-1258.88,-533.98) -1358.76,-730.71 cw(c-1254.04,-524.95) -1401.11,-702.92 cw(c-1250.32,-519.96) -1463.56,-623.6 cw(c-1263.92,-526.85) -1480.34,-575.61 cw(c-1254.28,-524.94) -1485.95,-525.03 cw(c-1247.63,-524.64) -1464.53,-425.88 cw(c-1261.59,-518.54) -1438.13,-382.15 cw(c-1254.34,-524.5) -1402.56,-345.41 cw(c-1249.61,-529.78) -1312.08,-298.52 cw(c-1253.77,-515.16) -1261.32,-290.93 cw(c-1253.8,-524.07) -1210.1,-294.94 cw(c-1255.24,-532.49) -1160.84,-309.88 cw(c-1253.7,-529.28) -1115.85,-334.96 cw(c-1246.35,-519.04) -1077.47,-369.39 cw(c-1252.87,-524.35) -1047.77,-411.61 cw(c-1260.54,-528.74) -1027.8,-459.32 cw(c-1257.34,-527.96) -1018.41,-510.21 cw(c-1244.73,-527.11) -1020.47,-561.97 cw(c-1252.45,-525.51) -1034.14,-612 cw(c-1260.98,-522.3) -1058.28,-658.01 cw(c-1258.58,-524.11) -1091.67,-697.87 cw(c-1249.88,-533.3) -1133.06,-729.42 cw(c-1253.26,-526.81) -1180.53,-750.89 cw(c-1256.31,-517.9) -1231.61,-761.65 cw(c-1256.2,-520.64) -1283.85,-761.32 cw(c-1257.74,-533.18) -1334.78,-749.5 cw(c-1255.06,-527) -1381.8,-726.5 cw(c-1249.99,-518.73) -1422.84,-693.85 cw(c-1251.83,-520.35) -1456.03,-653.19 cw(c-1262.45,-527.14) -1479.5,-606.2 cw(c-1256.55,-525.5) -1491.8,-555.08 cw(c-1246.66,-524.1) -1492.8,-502.4 cw(c-1248.8,-523.74) -1482.58,-450.68 cw(c-1260.74,-519.9) -1461.24,-402.42 cw(c-1256.28,-523.1) -1429.55,-360.15 cw(c-1248.69,-530.03) -1389.41,-325.66 cw(c-1249.61,-528.39) -1342.82,-300.46 cw(c-1254.23,-516.8) -1291.81,-286.06 cw(c-1253.98,-521.63) -1238.8,-283.52 cw(c-1254.5,-532.18) -1186.4,-292.52 cw(c-1253.9,-530.71) -1137.06,-312.44 cw(c-1247.95,-519.85) -1093.25,-342.7 cw(c-1251.09,-522.6) -1057.34,-382.11 cw(c-1259.78,-529.09) -1030.75,-428.43 cw(c-1258.54,-528.73) -1014.59,-479.38 cw(c-1246.48,-526.42) -1009.95,-532.67 cw(c-1249.91,-525.75) -1017.46,-585.69 cw(c-1260.72,-523.12) -1036.29,-635.92 cw(c-1259.92,-523.71) -1065.39,-681.06 cw(c-1250.55,-531.46) -1103.65,-718.77 cw(c-1251.77,-528.94) -1149.5,-746.92 cw(c-1256.75,-518.68) -1200.44,-764.49 cw(c-1256.77,-519.37) -1254,-770.87 cw(c-1256.77,-531.4) -1307.7,-765.4 cw(c-1255.74,-529.57) -1358.83,-747.95 cw(c-1250.89,-518.94) -1405.05,-719.77 cw(c-1251.25,-519.12) -1444.27,-682.39 cw(c-1260.41,-526.69) -1474.43,-637.34 cw(c-1259,-526.66) -1493.67,-586.58 cw(c-1247.45,-523.56) -1501.44,-532.77 cw(c-1247.51,-523.38) -1497.62,-478.48 cw(c-1259.03,-521.17) -1482.06,-426.29 cw(c-1258.79,-521.96) -1455.1,-378.9 cw(c-1248.82,-529.04) -1418.42,-338.44 cw(c-1248.51,-529.11) -1373.95,-306.65 cw(c-1254.07,-518.96) -1323.61,-285.27 cw(c-1254.74,-518.93) -1269.67,-275.79 cw(c-1253.82,-531.4) -1214.88,-278.27 cw(c-1253.73,-532) -1161.8,-292.34 cw(c-1249.51,-521.39) -1113.02,-317.61 cw(c-1249.49,-520.24) -1071.15,-353.28 cw(c-1258.71,-529.07) -1038,-397.28 cw(c-1259.39,-529.69) -1014.91,-447.37 cw(c-1248.69,-526.23) -1003.23,-501.3 cw(c-1247.02,-525.45) -1004.02,-556.54 cw(c-1259.96,-523.94) -1016.85,-610.37 cw(c-1261.18,-523.7) -1040.85,-660.3 cw(c-1251.85,-529.66) -1075.1,-703.86 cw(c-1249.65,-530.98) -1118.35,-738.63 cw(c-1256.87,-519.83) -1168.22,-763.14 cw(c-1257.57,-518.44) -1222.23,-776.54 cw(c-1256.24,-529.24) -1277.87,-777.92 cw(c-1255.94,-532.53) -1332.46,-766.72 cw(c-1251.87,-519.64) -1383.36,-743.81 cw(c-1251.08,-517.93) -1428.3,-710.58 cw(c-1258.43,-525.7) -1464.99,-668.41 cw(c-1261.4,-528.44) -1491.28,-619 cw(c-1248.66,-523.27) -1506.13,-564.94 cw(c-1246.52,-522.74) -1509.17,-508.9 cw(c-1256.99,-522.03) -1500.04,-453.51 cw(c-1261.71,-521.27) -1478.63,-401.53 cw(c-1249.42,-527.9) -1446.3,-355.43 cw(c-1247.4,-529.43) -1404.87,-317.21 cw(c-1253.41,-521.07) -1356.16,-288.81 cw(c-1256.1,-516.26) -1302.24,-272.1 cw(c-1253.35,-530.15) -1245.88,-267.61 cw(c-1253.24,-533.02) -1189.78,-275.21 cw(c-1250.68,-523.26) -1136.62,-294.72 cw(c-1248.34,-517.48) -1089.16,-325.74 cw(c-1257.41,-528.59) -1049.62,-366.49 cw(c-1259.82,-530.7) -1019.59,-414.76 cw(c-1250.85,-526.55) -1000.66,-468.39 cw(c-1244.21,-524.54) -994.27,-524.97 cw(c-1258.7,-524.62) -1000.49,-581.65 cw(c-1262.2,-524.05) -1018.64,-635.78 cw(c-1253.49,-528.22) -1048.01,-684.76 cw(c-1247.16,-532.5) -1087.7,-725.93 cw(c-1256.55,-521.28) -1135.54,-757.39 cw(c-1258.48,-517.92) -1189.05,-778 cw(c-1256.21,-527.07) -1245.75,-786.62 cw(c-1255.48,-535.36) -1303.01,-782.27 cw(c-1252.79,-520.87) -1357.97,-765.39 cw(c-1251.29,-516.92) -1408.16,-737.17 cw(c-1256.76,-524.31) -1451.13,-698.81 cw(c-1263.2,-530.58) -1484.43,-651.73 cw(c-1250.24,-523.39) -1506.54,-598.4 cw(c-1249.66,-522.6) -1514.65,-483.7 cw(c-1264.43,-521.31) -1499.55,-427.8 cw(c-1250.58,-526.74) -1472.43,-376.55 cw(c-1249.21,-526.97) -1388.87,-296.86 cw(c-1257.86,-514.31) -1335.95,-272.76 cw(c-1253.22,-528.46) -1278.94,-260.94 cw(c-1252.5,-530.15) -1163.8,-274.6 cw(c-1248.05,-514.98) -1111.27,-300.11 cw(c-1256.01,-527.55) -1065.64,-336.65 cw(c-1257.2,-529.52) -1002.52,-434.49 cw(c-1242.25,-523.16) -988.62,-491.45 cw(c-1256.95,-525.03) -987.7,-550.15 cw(c-1259.71,-525.3) -1023.01,-661.61 cw(c-1244.96,-533.01) -1058.17,-708.82 cw(c-1255.68,-522.92) -1102.99,-747.1 cw(c-1257.92,-520.55) -1211.83,-791.11 cw(c-1254.8,-530.16) -1329.17,-783.96 cw(c-1252.94,-518.93) -1432.88,-727.91 cw(c-1258.75,-527.81) -1502.44,-632.56 cw(c-1248.42,-521.9) -1525.44,-516.45 cw(c-1259.48,-523.01) -1496.21,-401.6 cw(c-1247.9,-527.44) -1421.09,-309.5 cw(c-1256.06,-519.18) -1313.53,-258.61 cw(c-1252,-531.42) -1194.21,-257.79 cw(c-1250.66,-519.41) -1086,-308.42 cw(c-1257.82,-530.7) -1009.01,-400.22 cw(c-1247.25,-523.93) -978.91,-516.33 cw(c-1260.99,-525.61) -1000.67,-634.64 cw(c-1248.63,-529.68) -1071.22,-732.23 cw(c-1258.97,-519.81) -1176.68,-791.1 cw(c-1253.29,-537.3) -1236.53,-801.88 cw(c-1253.82,-524.91) -1297.32,-798.99 cw(c-1253.06,-517.69) -1410.35,-755.07 cw(c-1262.97,-533.22) -1457,-715.68 cw(c-1254.09,-525.27) -1493.66,-666.8 cw(c-1247.59,-521.01) -1532.01,-551.25 cw(c-1265.86,-523.24) -1531.4,-489.96 cw(c-1254.61,-524.99) -1517.05,-430.32 cw(c-1246.71,-527.47) -1452.19,-326.72 cw(c-1260.02,-514.83) -1404.4,-287.96 cw(c-1254.53,-524.15) -1349.08,-260.89 cw(c-1250.94,-533.58) -1289.14,-246.29 cw(c-1251.33,-529.19) -1227.44,-244.78 cw(c-1249.98,-514.08) -1166.87,-256.93 cw(c-1253.51,-523.66) -1110.53,-282.4 cw(c-1258.67,-532.73) -1060.89,-319.44 cw(c-1255.75,-529.88) -1020.23,-366.21 cw(c-1243.21,-521.28) -990.87,-420.83 cw(c-1252.26,-524.4) -974.51,-480.7 cw(c-1262.87,-526.26) -971.41,-542.8 cw(c-1259.15,-526.67) -981.57,-604.18 cw(c-1244.52,-530.86) -1005.02,-661.85 cw(c-1252.09,-526.16) -1040.87,-712.81 cw(c-1260.54,-518.94) -1086.93,-754.95 cw(c-1258.68,-521.81) -1140.91,-786.35 cw(c-1252.6,-535.74) -1200.52,-805.12 cw(c-1253.64,-527.6) -1262.88,-810.01 cw(c-1253.45,-516.15) -1324.94,-801.34 cw(c-1254.39,-519.07) -1383.77,-779.67 cw(c-1261.24,-532.59) -1436.44,-745.59 cw(c-1256.06,-527.19) -1480.13,-700.48 cw(c-1246.85,-519.83) -1513.12,-646.93 cw(c-1249.4,-520.82) -1534,-587.55 cw(c-1264.11,-524.14) -1541.35,-525 cw(c-1257.41,-524.72) -1534.42,-462.35 cw(c-1245.54,-527.2) -1514.09,-402.57 cw(c-1247.61,-526.01) -1481.53,-348.43 cw(c-1259.47,-516.84) -1437.86,-302.71 cw(c-1256.16,-521.79) -1384.96,-267.98 cw(c-1250.36,-532.81) -1325.72,-245.46 cw(c-1250.68,-530.8) -1263,-236.01 cw(c-1251.16,-515.93) -1199.7,-240.53 cw(c-1252.75,-520.84) -1138.99,-259.22 cw(c-1257.68,-532.64) -1083.66,-290.63 cw(c-1256.53,-531.4) -1036.23,-333.11 cw(c-1245.48,-521.65) -999.22,-384.95 cw(c-1249.56,-523.13) -974.82,-443.86 cw(c-1262.11,-526.94) -963.73,-506.76 cw(c-1260.78,-527.06) -966.24,-570.62 cw(c-1246.37,-529.34) -982.64,-632.42 cw(c-1249.33,-527.43) -1012.59,-688.98 cw(c-1260.52,-520.01) -1054.15,-737.8 cw(c-1260.02,-520.84) -1105.15,-776.71 cw(c-1252.68,-533.27) -1163.45,-803.58 cw(c-1252.81,-530.58) -1226.35,-816.61 cw(c-1254.26,-516.9) -1290.7,-815.69 cw(c-1254.54,-517.45) -1353.43,-801.13 cw(c-1259.38,-530.86) -1411.5,-773.25 cw(c-1257.84,-529.79) -1461.84,-732.93 cw(c-1247.99,-519.73) -1502.29,-682.58 cw(c-1248.29,-519.67) -1531.16,-624.74 cw(c-1261.53,-524.42) -1546.75,-561.99 cw(c-1260.6,-525.04) -1547.79,-497.27 cw(c-1246.26,-526.25) -1534.71,-433.77 cw(c-1246.04,-526.1) -1508.45,-374.44 cw(c-1257.97,-519.02) -1469.9,-322.22 cw(c-1258.51,-519.53) -1420.51,-280.01 cw(c-1250.13,-531.61) -1363.03,-249.5 cw(c-1249.73,-532.02) -1300.34,-231.87 cw(c-1251.84,-518.52) -1235.29,-228.26 cw(c-1252.53,-517.53) -1171.04,-239.44 cw(c-1256.58,-531.98) -1110.68,-264.38 cw(c-1256.83,-532.89) -1056.93,-301.6 cw(c-1247.9,-522.82) -1012.53,-349.59 cw(c-1246.85,-521.13) -980.06,-406.43 cw(c-1260.84,-527.34) -960.74,-469.07 cw(c-1262.07,-527.8) -955.14,-534.44 cw(c-1248.84,-528.25) -963.85,-599.49 cw(c-1246.01,-528.22) -987.02,-660.97 cw(c-1259.96,-521.26) -1023.11,-715.98 cw(c-1261.4,-520.36) -1070.09,-762.13 cw(c-1253.46,-530.68) -1125.96,-797.01 cw(c-1251.26,-533.66) -1188.33,-818.43 cw(c-1254.84,-518.19) -1253.96,-825.71 cw(c-1255.07,-516.13) -1319.71,-818.89 cw(c-1257.91,-528.59) -1382.43,-798.01 cw(c-1259.2,-532.99) -1438.9,-763.49 cw(c-1249.4,-520.16) -1486.51,-717.38 cw(c-1247.66,-518.42) -1523.29,-662.17 cw(c-1258.86,-524.07) -1547.27,-600.31 cw(c-1263.93,-526.08) -1556.71,-534.55 cw(c-1247.55,-525.45) -1551.51,-468.25 cw(c-1244.72,-525.76) -1532.33,-404.48 cw(c-1255.98,-520.81) -1499.84,-346.35 cw(c-1261.46,-517.66) -1455.04,-296.98 cw(c-1250.39,-530.05) -1400.43,-258.59 cw(c-1248.63,-532.77) -1338.84,-232.64 cw(c-1251.92,-521.18) -1273.11,-220.58 cw(c-1253.01,-514.09) -1206.27,-223.63 cw(c-1255.54,-530.72) -1141.65,-241.3 cw(c-1256.66,-534.18) -1082.19,-272.34 cw(c-1249.97,-524.47) -1030.8,-315.45 cw(c-1244.57,-518.56) -990.39,-369.08 cw(c-1259.16,-527.3) -962.73,-430.36 cw(c-1262.91,-528.76) -948.7,-496.2 cw(c-1251.43,-527.76) -949.16,-563.51 cw(c-1242.62,-528.28) -964.77,-629.07 cw(c-1258.79,-522.55) -994.47,-689.66 cw(c-1262.64,-520.37) -1036.41,-742.62 cw(c-1254.75,-528.39) -1088.76,-785.33 cw(c-1249.13,-536.21) -1149.44,-815.21 cw(c-1255.05,-519.98) -1215.29,-831 cw(c-1255.88,-515.23) -1283.07,-832.43 cw(c-1257.01,-526.14) -1349.59,-819.27 cw(c-1259.73,-536.19) -1411.51,-791.47 cw(c-1250.94,-521.2) -1465.84,-750.65 cw(c-1250.97,-520.21) -1542.67,-639.3 cw(c-1266.62,-527.73) -1560.8,-573.63 cw(c-1249.4,-524.95) -1563.99,-505.51 cw(c-1248.1,-524.35) -1527.02,-374.87 cw(c-1264.36,-516.75) -1487.86,-318.84 cw(c-1251.24,-528.27) -1437.22,-272.81 cw(c-1249.63,-529.36) -1312.54,-217.83 cw(c-1254.2,-511.43) -1244.16,-212.26 cw(c-1254.73,-528.86) -1176.18,-221.98 cw(c-1254.7,-531.35) -1053.92,-283.22 cw(c-1244.75,-517.49) -1005.84,-332.51 cw(c-1257.44,-527.46) -969.76,-391.26 v2@-914.51,-446.51
  Top Layer w27.56: v2(-856,-624) -835,-624 -819.92,-608.92 -819.92,-559.61 ; v2(-851,-440) -819.92,-471.08 -819.92,-510.39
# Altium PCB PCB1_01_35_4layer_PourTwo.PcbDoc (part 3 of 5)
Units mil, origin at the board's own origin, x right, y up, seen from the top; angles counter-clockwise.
Board outline 1043.31 x 669.29 mil, 4 copper layers (Top Layer, Layer 1, Layer 2, Bottom Layer), stack 23.756 mil thick; 0 components, 1 nets, 8 pads, 85 vias.

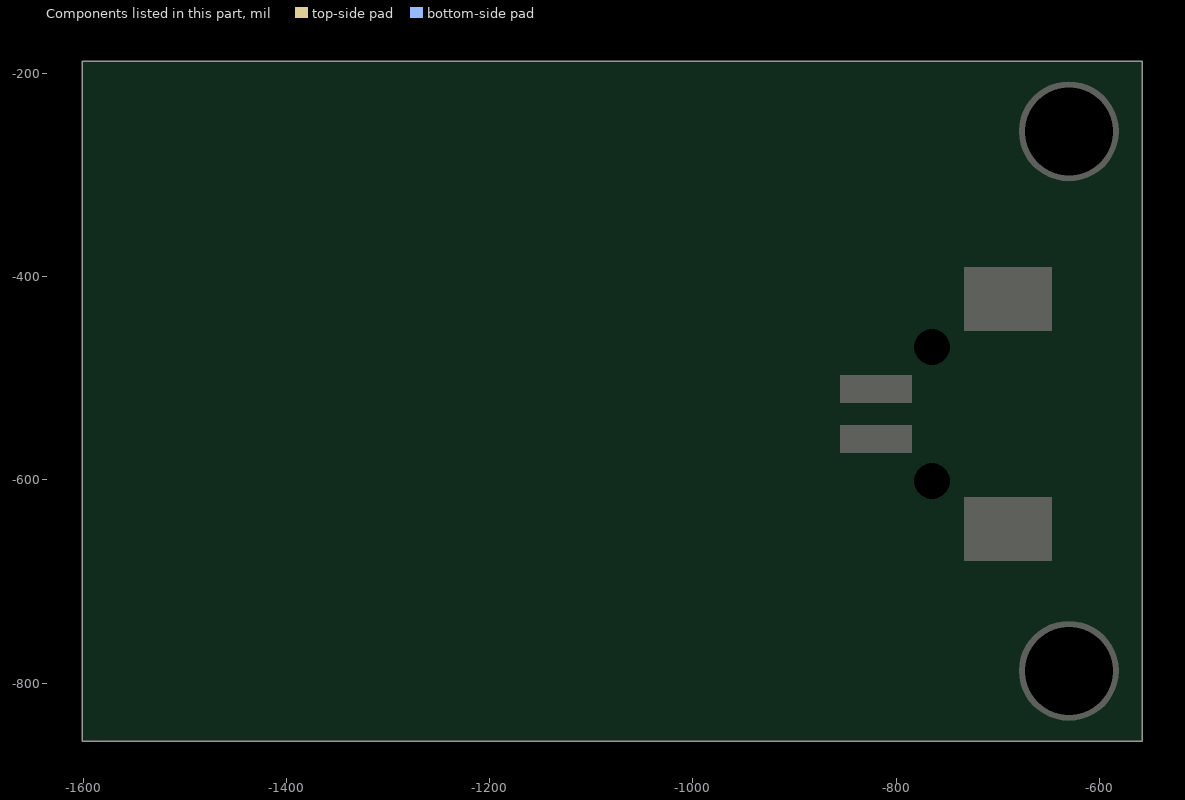
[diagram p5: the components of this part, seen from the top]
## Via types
v1: diameter 19.68, hole 11.81, Top Layer to Bottom Layer, tented both sides, 70 vias
v2: diameter 39.37, hole 19.68, Top Layer to Bottom Layer, 9 vias
v3: diameter 19.68, hole 11.81, Top Layer to Bottom Layer, 6 vias

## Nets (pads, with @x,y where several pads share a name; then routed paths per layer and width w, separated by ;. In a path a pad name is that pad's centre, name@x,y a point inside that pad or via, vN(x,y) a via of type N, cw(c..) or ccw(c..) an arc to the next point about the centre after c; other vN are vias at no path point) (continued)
copper on no net: (continued)
  Layer 2 w3.94: -1375.27,-569.03 ccw(c-1249.41,-522.43) -1362.67,-594.44 ccw(c-1255.25,-526.24) -1344.96,-616.47 ccw(c-1259.89,-530.67) -1322.74,-633.86 ccw(c-1255.73,-523.83) -1297.25,-645.79 ccw(c-1254.06,-519.19) -1269.82,-652.02 ccw(c-1254.19,-521.1) -1241.77,-652.37 ccw(c-1253.38,-528.94) -1214.4,-646.62 ccw(c-1252.72,-531.94) -1189.13,-634.78 ccw(c-1258.28,-523.31) -1149.3,-596.33 ccw(c-1256.53,-524.2) -1136.37,-571.78 ccw(c-1248.56,-527.29) -1129.19,-545.05 ccw(c-1249.37,-527.52) -1128.34,-517.47 ccw(c-1256.8,-528.08) -1133.53,-490.41 ccw(c-1258.92,-528.63) -1144.28,-465.06 ccw(c-1254.86,-526.29) -1160.09,-442.65 ccw(c-1248.34,-520.49) -1180.46,-424.36 ccw(c-1250.61,-524.11) -1204.4,-411.26 ccw(c-1253.18,-530.19) -1230.58,-403.65 ccw(c-1253.4,-530.89) -1257.74,-401.69 ccw(c-1254.29,-520.78) -1309.82,-415.37 ccw(c-1252.35,-523.37) -1332.1,-430.6 ccw(c-1248.78,-527.65) -1350.6,-450.23 ccw(c-1249.43,-527.27) -1364.54,-473.25 ccw(c-1255.68,-524.42) -1373.18,-498.64 ccw(c-1260.94,-523.06) -1375.78,-525.28 ccw(c-1253.24,-522.92) -1372.36,-551.76 ccw(c-1248.95,-521.97) -1363.41,-576.89 ccw(c-1250.87,-522.99) -1349.43,-599.52 ccw(c-1256.9,-527.75) -1330.91,-618.5 ccw(c-1258.45,-529.14) -1308.58,-632.69 ccw(c-1254.47,-520.55) -1257.56,-645.03 ccw(c-1254.32,-522.89) -1231.36,-642.89 ccw(c-1252.72,-530.99) -1206.33,-635.04 ccw(c-1253.64,-529.68) -1183.85,-621.7 ccw(c-1257.76,-524.16) -1164.84,-603.81 ccw(c-1259.02,-522.96) -1150.03,-582.34 ccw(c-1254.81,-525.16) -1140.13,-558.32 ccw(c-1246.92,-527.43) -1135.88,-532.74 ccw(c-1251.64,-527.38) -1137.57,-506.96 ccw(c-1257.59,-528.38) -1144.78,-482.16 ccw(c-1257.94,-528.43) -1156.99,-459.47 ccw(c-1250.14,-522.48) -1194.37,-424.82 ccw(c-1251.61,-525.89) -1217.84,-414.76 ccw(c-1253.14,-530.66) -1242.9,-409.93 ccw(c-1253.14,-529.61) -1268.36,-410.46 ccw(c-1254.06,-522.94) -1293.01,-416.46 ccw(c-1255.38,-518.68) -1315.59,-427.91 ccw(c-1249.89,-526.55) -1350.53,-463.95 ccw(c-1250.69,-526.35) -1361.5,-486.58 ccw(c-1257.73,-523.88) -1367.25,-510.98 ccw(c-1258.81,-523.44) -1367.23,-535.99 ccw(c-1250.2,-522.3) -1351.23,-582.94 ccw(c-1252.42,-523.84) -1336.25,-602.76 ccw(c-1258.14,-529.29) -1317.31,-618.73 ccw(c-1257.12,-527.25) -1295.28,-629.89 ccw(c-1254.86,-521.34) -1271.38,-635.99 ccw(c-1254.59,-520.05) -1246.77,-636.93 ccw(c-1254.2,-524.8) -1222.61,-632.65 ccw(c-1252.05,-532.14) -1200.09,-623.07 ccw(c-1254.67,-527.83) -1180.4,-608.66 ccw(c-1258.32,-523.76) -1164.29,-590.38 ccw(c-1258.27,-523.69) -1152.39,-569.17 ccw(c-1249.45,-526.97) -1143.73,-521.88 ccw(c-1253.5,-527.49) -1147.59,-498.09 ccw(c-1257.83,-528.62) -1156.43,-475.69 ccw(c-1256.71,-527.94) -1169.72,-455.7 ccw(c-1251.69,-523.7) -1186.96,-439.12 ccw(c-1249.37,-521.06) -1207.5,-426.95 ccw(c-1252.82,-529.26) -1253.83,-417.37 ccw(c-1253.05,-528.07) -1277.37,-420.07 ccw(c-1254.68,-521.05) -1299.68,-427.85 ccw(c-1254.53,-520.66) -1319.55,-440.5 ccw(c-1249.48,-526.73) -1348.8,-476.94 ccw(c-1252.21,-525.53) -1356.99,-498.85 ccw(c-1259.49,-523.71) -1360.1,-521.97 ccw(c-1256.66,-523.53) -1357.83,-545.11 ccw(c-1251,-522.38) -1350.61,-567.17 ccw(c-1250.11,-522.07) -1338.95,-587.2 ccw(c-1253.9,-524.93) -1323.36,-604.22 ccw(c-1258.54,-530.2) -1304.38,-617.26 ccw(c-1256.2,-525.54) -1283.01,-625.61 ccw(c-1254.86,-520.79) -1260.37,-629.19 ccw(c-1254.8,-521.11) -1237.53,-627.95 ccw(c-1253.84,-526.67) -1215.59,-621.85 ccw(c-1251.98,-531.64) -1195.65,-610.95 ccw(c-1255.66,-526.46) -1178.73,-595.89 ccw(c-1258.56,-523.76) -1165.41,-577.6 ccw(c-1257.19,-524.46) -1156.25,-556.99 ccw(c-1251.11,-526.36) -1151.8,-534.96 ccw(c-1248.53,-526.84) -1152.52,-512.55 ccw(c-1256.58,-528.19) -1168.25,-471 ccw(c-1255.38,-527.19) -1182.24,-453.7 ccw(c-1250.54,-522.26) -1199.64,-439.95 ccw(c-1250.54,-522.79) -1219.67,-430.59 ccw(c-1252.46,-528.39) -1241.22,-425.86 ccw(c-1252.73,-530.12) -1263.25,-425.75 ccw(c-1253.17,-526.39) -1284.71,-430.29 ccw(c-1255.4,-519.7) -1304.57,-439.48 ccw(c-1253.53,-522.38) -1321.74,-452.92 ccw(c-1249.9,-526.16) -1335.57,-469.72 ccw(c-1249.45,-526.54) -1345.56,-489.02 ccw(c-1257.2,-523.99) -1351.94,-531.47 ccw(c-1254.88,-523.39) -1347.8,-552.57 ccw(c-1250.66,-522.13) -1339.25,-572.27 ccw(c-1251.13,-522.48) -1326.8,-589.7 ccw(c-1255.21,-526.18) -1310.96,-603.97 ccw(c-1257.93,-529.71) -1292.33,-614.24 ccw(c-1255.64,-524.13) -1271.93,-620.04 ccw(c-1255,-520.72) -1250.8,-621.39 ccw(c-1254.86,-522.43) -1229.92,-618.28 ccw(c-1253.26,-528.36) -1210.3,-610.73 ccw(c-1252.66,-530.06) -1192.98,-598.91 ccw(c-1257.63,-524.53) -1168.07,-565.65 ccw(c-1255.87,-525.15) -1161.44,-545.94 ccw(c-1249.42,-526.53) -1159.33,-525.31 ccw(c-1250.51,-526.79) -1162,-504.83 ccw(c-1255.75,-528.05) -1169.07,-485.47 ccw(c-1257.01,-528.59) -1180.02,-468.04 ccw(c-1254.09,-526.22) -1194.35,-453.4 ccw(c-1249.94,-521.13) -1211.55,-442.37 ccw(c-1251.38,-524.42) -1230.73,-435.58 ccw(c-1252.49,-528.99) -1250.9,-433.09 ccw(c-1252.57,-529.26) -1271.09,-434.88 ccw(c-1254.47,-521.71) -1307.7,-451.12 ccw(c-1252.57,-523.67) -1322.23,-464.94 ccw(c-1249.62,-526.23) -1333.47,-481.52 ccw(c-1250.37,-525.91) -1340.95,-500.02 ccw(c-1255.5,-524.5) -1344.26,-519.63 ccw(c-1259.12,-524.13) -1342.99,-539.41 ccw(c-1251.86,-522.63) -1327.87,-575.64 ccw(c-1252.26,-523.14) -1315,-590.5 ccw(c-1256.23,-527.48) -1299.25,-602.14 ccw(c-1256.96,-528.25) -1281.31,-609.82 ccw(c-1255.15,-521.8) -1242.76,-612.79 ccw(c-1254.73,-523.87) -1223.97,-608.16 ccw(c-1252.56,-529.71) -1206.74,-599.51 ccw(c-1253.62,-528.48) -1192,-587.18 ccw(c-1257.11,-525.1) -1180.33,-571.98 ccw(c-1257.95,-524.51) -1172.12,-554.71 ccw(c-1254.42,-525.69) -1167.79,-536.17 ccw(c-1248.43,-526.41) -1167.72,-517.18 ccw(c-1252.17,-526.95) -1171.97,-498.76 ccw(c-1256.15,-528.29) -1180.07,-481.72 ccw(c-1256.17,-528.24) -1191.52,-466.78 ccw(c-1251.1,-522.89) -1222.48,-446.22 ccw(c-1251.89,-525.77) -1240.54,-441.72 ccw(c-1252.4,-529.15) -1259.1,-441.18 ccw(c-1252.54,-528.15) -1277.31,-444.52 ccw(c-1254.04,-523.26) -1294.29,-451.7 ccw(c-1255.27,-520.69) -1309.13,-462.54 ccw(c-1250.58,-525.54) -1329.94,-492.38 ccw(c-1251.51,-525.33) -1335.15,-509.82 ccw(c-1257.02,-524.35) -1336.42,-527.91 ccw(c-1257.4,-524.14) -1333.5,-545.74 ccw(c-1251.68,-522.43) -1316.67,-577.32 ccw(c-1253.36,-524) -1303.73,-589.69 ccw(c-1256.97,-528.77) -1288.42,-598.83 ccw(c-1257.05,-528.33) -1271.51,-604.13 ccw(c-1255.83,-521.09) -1236.38,-603.33 ccw(c-1255.5,-521.64) -1219.77,-597.54 ccw(c-1251.37,-529.5) -1192.53,-576.05 ccw(c-1253.41,-528.33) -1183.43,-561.28 ccw(c-1259,-525.78) -1175.53,-527.75 ccw(c-1256.42,-525.73) -1176.93,-510.6 ccw(c-1250.31,-524.53) -1182.04,-494.25 ccw(c-1247.69,-523.58) -1190.81,-479.59 ccw(c-1252.07,-526.96) -1202.61,-467.37 ccw(c-1254.81,-530.19) -1216.73,-457.93 ccw(c-1254.97,-530.36) -1232.45,-451.61 ccw(c-1253.87,-526.33) -1249.04,-448.75 ccw(c-1253.5,-519.92) -1265.8,-449.68 ccw(c-1253.17,-520.5) -1281.78,-454.5 ccw(c-1251.04,-525.48) -1296.26,-462.72 ccw(c-1249.21,-528.11) -1308.68,-473.77 ccw(c-1250.07,-527.41) -1318.53,-487.1 ccw(c-1254.44,-524.89) -1325.27,-502.12 ccw(c-1260.05,-523.07) -1328.38,-518.25 ccw(c-1256.53,-523.21) -1327.65,-534.56 ccw(c-1250.38,-522.13) -1316,-564.79 ccw(c-1251.64,-523.11) -1305.81,-577.37 ccw(c-1255.6,-527.13) -1293.2,-587.39 ccw(c-1257.78,-530.39) -1278.64,-594.18 ccw(c-1256.26,-525.69) -1263.01,-597.42 ccw(c-1255.82,-521.41) -1247.07,-597.26 ccw(c-1255.85,-520.63) -1231.53,-593.83 ccw(c-1254.71,-523.9) -1217.13,-587.27 ccw(c-1251.65,-529.01) -1204.61,-577.72 ccw(c-1251.19,-529.79) -1194.72,-565.54 ccw(c-1255.49,-527.05) -1187.85,-551.52 ccw(c-1258.69,-525.84) -1184.08,-536.38 ccw(c-1258.21,-525.86) -1183.5,-520.85 ccw(c-1253.86,-525.52) -1186.21,-505.64 ccw(c-1248.23,-523.86) -1192.27,-491.49 ccw(c-1250.02,-525.06) -1201.43,-479.22 ccw(c-1254.45,-529.42) -1226.42,-462 ccw(c-1254.33,-528.71) -1240.96,-457.65 ccw(c-1253.23,-521.05) -1270.84,-458.92 ccw(c-1252.37,-523.05) -1284.65,-464.64 ccw(c-1250.33,-526.81) -1296.88,-473.18 ccw(c-1249.55,-527.78) -1307.06,-484.03 ccw(c-1251.78,-526.15) -1314.73,-496.7 ccw(c-1256.72,-523.87) -1319.4,-510.66 ccw(c-1258.83,-523.25) -1320.66,-525.27 ccw(c-1254.12,-523.1) -1318.59,-539.71 ccw(c-1250.68,-522.25) -1313.52,-553.37 ccw(c-1250.59,-522.27) -1305.77,-565.65 ccw(c-1253.47,-524.58) -1295.68,-575.96 ccw(c-1256.99,-528.9) -1283.58,-583.72 ccw(c-1256.82,-528.14) -1270.07,-588.38 ccw(c-1255.83,-523.69) -1255.92,-589.93 ccw(c-1255.78,-521.06) -1241.78,-588.5 ccw(c-1255.51,-522.09) -1228.29,-584.2 ccw(c-1253.7,-526.11) -1216.12,-577.17 ccw(c-1250.75,-530.16) -1205.91,-567.56 ccw(c-1253.2,-528.22) -1198.28,-555.93 ccw(c-1257.87,-525.95) -1191.24,-529.25 ccw(c-1256.34,-525.92) -1192,-515.48 ccw(c-1251.51,-525.11) -1195.71,-502.3 ccw(c-1248.52,-524.01) -1202.37,-490.38 ccw(c-1251.9,-526.48) -1211.52,-480.38 ccw(c-1254.27,-529.14) -1222.57,-472.56 ccw(c-1254.58,-529.59) -1234.96,-467.21 ccw(c-1253.71,-526.68) -1248.11,-464.57 ccw(c-1253.27,-521.57) -1261.45,-464.93 ccw(c-1253.17,-521) -1274.26,-468.39 ccw(c-1251.6,-524.94) -1285.91,-474.6 ccw(c-1250.06,-527.27) -1295.99,-483.11 ccw(c-1250.46,-526.95) -1304.06,-493.46 ccw(c-1253.7,-524.97) -1309.73,-505.21 ccw(c-1258.4,-523.32) -1312.55,-517.89 ccw(c-1256.43,-523.4) -1312.34,-530.78 ccw(c-1251.38,-522.63) -1303.77,-554.85 ccw(c-1251.96,-523.13) -1296,-564.97 ccw(c-1256.54,-527.88) -1275.01,-578.79 ccw(c-1256.1,-526) -1262.82,-581.67 ccw(c-1255.65,-522.53) -1250.31,-581.86 ccw(c-1255.69,-521.59) -1238.07,-579.48 ccw(c-1254.94,-523.89) -1226.66,-574.64 ccw(c-1252.66,-527.94) -1216.67,-567.45 ccw(c-1251.66,-529.27) -1208.67,-558.16 ccw(c-1254.87,-527.1) -1203.03,-547.37 ccw(c-1257.52,-526.03) -1199.79,-535.65 ccw(c-1257.47,-525.99) -1199.04,-523.57 ccw(c-1254.3,-525.82) -1200.83,-511.68 ccw(c-1249.74,-524.6) -1205.23,-500.56 ccw(c-1250.37,-525.11) -1212.08,-490.85 ccw(c-1253.15,-527.57) -1220.86,-482.93 ccw(c-1254.4,-529.24) -1231.08,-477.03 ccw(c-1254.04,-528.33) -1242.24,-473.38 ccw(c-1253.28,-524.65) -1253.83,-472.21 ccw(c-1253.31,-520.5) -1265.34,-473.73 ccw(c-1252.59,-523.07) -1276.08,-477.85 ccw(c-1250.62,-526.73) -1293.69,-492.33 ccw(c-1251.77,-525.92) -1299.82,-501.91 ccw(c-1255.48,-524.09) -1303.68,-512.51 ccw(c-1257.89,-523.4) -1304.96,-523.68 ccw(c-1254.49,-523.38) -1303.66,-534.75 ccw(c-1251.71,-522.77) -1300.05,-545.27 ccw(c-1251.37,-522.65) -1294.36,-554.79 ccw(c-1253.43,-524.24) -1286.87,-562.84 ccw(c-1256.24,-527.5) -1277.83,-568.99 ccw(c-1256.5,-527.69) -1267.66,-572.81 ccw(c-1255.68,-524.41) -1256.96,-574.26 ccw(c-1255.59,-522.22) -1246.22,-573.42 ccw(c-1255.46,-522.72) -1235.94,-570.42 ccw(c-1254.22,-525.66) -1226.6,-565.34 ccw(c-1251.87,-529.03) -1218.7,-558.3 ccw(c-1253.21,-527.97) -1212.72,-549.68 ccw(c-1256.79,-526.13) -1206.95,-529.75 ccw(c-1256.03,-526.09) -1207.27,-519.41 ccw(c-1250.66,-525.12) -1214.54,-500.41 ccw(c-1251.9,-526.17) -1221.19,-492.77 ccw(c-1253.77,-528.17) -1229.29,-486.75 ccw(c-1254.14,-528.73) -1238.43,-482.55 ccw(c-1253.51,-526.77) -1248.16,-480.35 ccw(c-1253.09,-522.96) -1258.07,-480.36 ccw(c-1253.1,-521.75) -1267.64,-482.68 ccw(c-1252.05,-524.58) -1276.37,-487.07 ccw(c-1250.87,-526.45) -1283.95,-493.18 ccw(c-1250.99,-526.38) -1290.08,-500.68 ccw(c-1253.21,-524.96) -1294.46,-509.24 ccw(c-1256.82,-523.59) -1296.78,-518.51 ccw(c-1256.06,-523.58) -1296.86,-527.98 ccw(c-1252.32,-523.09) -1290.99,-545.73 ccw(c-1252.45,-523.29) -1285.48,-553.25 ccw(c-1254.71,-525.38) -1278.55,-559.37 ccw(c-1256.63,-528.07) -1270.44,-563.7 ccw(c-1255.88,-526.05) -1261.64,-566.01 ccw(c-1255.48,-522.93) -1243.68,-564.82 ccw(c-1255.08,-524.12) -1235.36,-561.5 ccw(c-1253.49,-527.08) -1228.02,-556.49 ccw(c-1253.41,-527.43) -1222.07,-549.94 ccw(c-1255.06,-526.2) -1217.74,-542.3 ccw(c-1254.28,-526.41) -1214.45,-525.31 ; -1375.27,-569.02 cw(c-1249.07,-522.2) -1382.29,-541.48 cw(c-1255.15,-523.01) -1383.24,-513.06 cw(c-1261.75,-522.61) -1377.69,-485.09 cw(c-1253.62,-525.27) -1365.97,-459.03 cw(c-1248.52,-528.17) -1348.9,-435.99 cw(c-1249.3,-527.33) -1327.35,-417.01 cw(c-1253.39,-521.42) -1302.19,-403.13 cw(c-1255.05,-518.12) -1274.43,-395.37 cw(c-1253.57,-527.19) -1245.58,-393.97 cw(c-1253.6,-530.87) -1190.02,-409.36 cw(c-1249.17,-522.14) -1166,-425.7 cw(c-1249.55,-522.01) -1146.33,-447.17 cw(c-1256.65,-527.23) -1131.81,-472.5 cw(c-1257.9,-528.08) -1120.11,-529.56 cw(c-1246.86,-527.99) -1123.87,-558.67 cw(c-1250.79,-526.69) -1134.22,-586.21 cw(c-1257.99,-523.1) -1150.34,-610.92 cw(c-1259.3,-522.16) -1171.32,-631.76 cw(c-1255.92,-526.51) -1196.28,-647.66 cw(c-1252.28,-533.87) -1224.24,-657.56 cw(c-1253.77,-526.62) -1253.78,-660.85 cw(c-1253.86,-519.58) -1283.43,-657.72 cw(c-1253.96,-519.54) -1311.82,-648.43 cw(c-1256.78,-525.65) -1337.56,-633.26 cw(c-1260.46,-530.8) -1359.24,-612.56 cw(c-1253.34,-524.92) -1375.74,-587.48 cw(c-1248.19,-522.18) -1386.58,-559.37 cw(c-1249.76,-522.49) -1391.28,-529.57 cw(c-1257.53,-522.82) -1389.4,-499.45 cw(c-1260.5,-522.62) -1380.63,-470.47 cw(c-1251.69,-526.38) -1365.63,-444.11 cw(c-1248.89,-528.13) -1320.72,-403.51 cw(c-1254.34,-518.98) -1292.71,-391.44 cw(c-1254.37,-520.22) -1262.62,-386.11 cw(c-1253.75,-529.24) -1232,-387.49 cw(c-1253.59,-530.24) -1174.87,-409.22 cw(c-1247.38,-520.25) -1151.21,-428.95 cw(c-1251.37,-523.64) -1132.65,-453.6 cw(c-1258.36,-527.87) -1119.82,-481.78 cw(c-1259.55,-528.37) -1113.16,-512.08 cw(c-1253.48,-527.78) -1113.11,-543.11 cw(c-1248.76,-527.83) -1133.8,-601.43 cw(c-1259.07,-522.02) -1153.23,-625.93 cw(c-1258.86,-522.37) -1177.4,-645.84 cw(c-1254.89,-528.53) -1205.31,-660.09 cw(c-1252.61,-533.98) -1235.81,-667.62 cw(c-1253.86,-524.21) -1267.28,-668.12 cw(c-1253.42,-518.48) -1298.25,-661.93 cw(c-1254.14,-520.43) -1327.25,-649.36 cw(c-1258.33,-527.68) -1352.83,-630.75 cw(c-1259.49,-529.49) -1373.52,-606.71 cw(c-1251.31,-523.87) -1388.42,-578.63 cw(c-1248.75,-522.58) -1399.11,-516.12 cw(c-1260.25,-522.26) -1394.04,-484.58 cw(c-1258.17,-523.26) -1381.84,-454.98 cw(c-1250.04,-527.66) -1363.44,-428.68 cw(c-1249.51,-527.66) -1312.17,-390.37 cw(c-1254.94,-516.47) -1281.44,-380.55 cw(c-1253.97,-522.75) -1249.23,-378 cw(c-1254.15,-531.02) -1217.13,-382.46 cw(c-1254.26,-531.94) -1186.62,-393.57 cw(c-1251.24,-525.95) -1159.18,-410.95 cw(c-1249.14,-522.41) -1119.28,-461.96 cw(c-1259.83,-528.17) -1108.53,-492.86 cw(c-1258.99,-528.08) -1104.49,-525.38 cw(c-1251.04,-528.02) -1107.57,-558.01 cw(c-1245.77,-528.86) -1118.05,-589.17 cw(c-1255.19,-524.45) -1135.25,-617.24 cw(c-1259.71,-521.09) -1158.07,-641.11 cw(c-1258.11,-523.14) -1185.42,-659.67 cw(c-1253.95,-531.1) -1216.2,-671.82 cw(c-1253.26,-532.09) -1249.02,-676.59 cw(c-1253.63,-521.89) -1282.16,-674 cw(c-1253.48,-519.52) -1343.32,-648.42 cw(c-1260.36,-529.77) -1368.31,-626.25 cw(c-1257.53,-527.76) -1387.57,-598.9 cw(c-1249.32,-523.17) -1400.47,-567.92 cw(c-1247.14,-522.4) -1406.6,-534.86 cw(c-1253.02,-522.76) -1405.56,-501.24 cw(c-1262.59,-521.41) -1396.99,-468.64 cw(c-1255.71,-524.35) -1381.19,-438.81 cw(c-1248.78,-528.95) -1359.28,-412.98 cw(c-1248.34,-529.24) -1332.41,-392.29 cw(c-1252.1,-522.95) -1301.72,-377.83 cw(c-1254.82,-515.37) -1268.46,-370.69 cw(c-1253.91,-525.41) -1234.4,-371.24 cw(c-1254.69,-532.37) -1201.13,-379.05 cw(c-1254.14,-531.16) -1170.2,-393.68 cw(c-1249.6,-523.88) -1143.16,-414.67 cw(c-1246.63,-520.37) -1121.59,-441.36 cw(c-1255.78,-526.21) -1106.47,-472.23 cw(c-1259.86,-527.92) -1097.14,-540.18 cw(c-1248.2,-528.66) -1103.67,-574.1 cw(c-1248.03,-528.25) -1117.85,-605.67 cw(c-1257.04,-522.98) -1138.66,-633.43 cw(c-1258.58,-521.98) -1195.39,-673.01 cw(c-1253.28,-534.03) -1228.9,-682.59 cw(c-1253.67,-529.35) -1263.77,-684.25 cw(c-1253.14,-519.84) -1298.26,-678.29 cw(c-1252.72,-517.92) -1330.81,-665.22 cw(c-1255.86,-523.64) -1359.83,-645.51 cw(c-1262.24,-531.14) -1383.72,-619.71 cw(c-1255.19,-526.22) -1401.15,-589.12 cw(c-1247.57,-522.82) -1411.65,-555.4 cw(c-1247.53,-522.69) -1414.86,-520.18 cw(c-1255.51,-522.48) -1410.43,-485.09 cw(c-1263,-520.85) -1398.09,-451.83 cw(c-1253.37,-525.79) -1378.57,-422.16 cw(c-1247.97,-530.11) -1353.12,-397.24 cw(c-1249.03,-528.58) -1322.97,-378.19 cw(c-1253.02,-520.28) -1289.39,-366.14 cw(c-1253.69,-519.46) -1253.84,-362.04 cw(c-1253.58,-528.71) -1218.17,-365.84 cw(c-1253.85,-530.51) -1184.06,-377.15 cw(c-1251.13,-524.75) -1153.17,-395.57 cw(c-1249.16,-521.64) -1127.17,-420.52 cw(c-1256.2,-527.58) -1107.24,-450.63 cw(c-1257.95,-528.62) -1094.13,-484.35 cw(c-1251.89,-527.08) -1088.59,-520.12 cw(c-1247.77,-526.6) -1091.26,-556.3 cw(c-1256.95,-524.94) -1101.83,-591.08 cw(c-1259.07,-524.17) -1119.58,-622.88 cw(c-1254.12,-527.79) -1143.78,-650.14 cw(c-1250.84,-531.02) -1173.54,-671.29 cw(c-1255.46,-522.78) -1207.3,-685.41 cw(c-1256.28,-520.44) -1243.36,-692.04 cw(c-1255.93,-526.44) -1280.03,-690.75 cw(c-1256.4,-531.47) -1315.54,-681.25 cw(c-1252.96,-522.57) -1348.14,-664.11 cw(c-1251.55,-520.26) -1376.41,-640.4 cw(c-1255.86,-524.26) -1398.95,-611.13 cw(c-1260.43,-527.31) -1414.36,-577.5 cw(c-1251.29,-524.27) -1421.99,-541.22 cw(c-1250.83,-523.85) -1413.49,-467.82 cw(c-1259.75,-521.37) -1397.29,-434.28 cw(c-1251.54,-526.51) -1374.05,-405.1 cw(c-1250.7,-526.82) -1311.67,-364.61 cw(c-1254.58,-518.03) -1275.27,-355.64 cw(c-1253.31,-527.67) -1237.72,-354.95 cw(c-1253.05,-528.83) -1166.31,-377.35 cw(c-1248.55,-519.95) -1136,-399.83 cw(c-1255.2,-527.09) -1111.38,-428.5 cw(c-1256.19,-528.19) -1082.95,-498.26 cw(c-1246.16,-525.98) -1080.92,-536.18 cw(c-1255.89,-525.39) -1087.37,-573.66 cw(c-1257.68,-525.24) -1123.23,-640.46 cw(c-1249.37,-531.77) -1151.33,-666.35 cw(c-1255.1,-523.92) -1184.53,-685.4 cw(c-1256.24,-522.14) -1259.33,-700.42 cw(c-1256.01,-532.98) -1297.44,-695.25 cw(c-1253.61,-523.62) -1333.5,-681.72 cw(c-1252.82,-521.32) -1393.13,-633.36 cw(c-1257.34,-526.11) -1426.2,-563.86 cw(c-1249.95,-523.55) -1426.94,-486.6 cw(c-1256.87,-523.01) -1394.27,-416.38 cw(c-1249.92,-527.28) -1334.84,-366.27 cw(c-1254.03,-521.28) -1259.45,-346.55 cw(c-1252.89,-529.71) -1182.48,-360.5 cw(c-1250.71,-522.42) -1118.84,-406.3 cw(c-1256.74,-528.89) -1080.3,-474.92 cw(c-1249.4,-525.86) -1074.99,-553.62 cw(c-1258.55,-525.28) -1103.48,-627.51 cw(c-1251.3,-529.23) -1161.07,-682.1 cw(c-1256.83,-521.52) -1236.63,-707.39 cw(c-1255.3,-533.41) -1276.77,-707.06 cw(c-1254.11,-525.07) -1315.88,-697.75 cw(c-1252.73,-520.48) -1383.93,-655.39 cw(c-1260.97,-529.27) -1409.42,-624.07 cw(c-1254.02,-525.04) -1427.28,-587.79 cw(c-1249.28,-523.07) -1438.07,-507.87 cw(c-1261.33,-522.3) -1430.15,-468.03 cw(c-1253.97,-524.89) -1413.48,-430.92 cw(c-1249.13,-527.47) -1358.44,-371.32 cw(c-1256.2,-517.68) -1322.48,-351.9 cw(c-1253.65,-524.68) -1283.03,-341.03 cw(c-1252.47,-531.29) -1242.07,-338.88 cw(c-1252.18,-528.35) -1201.55,-345.49 cw(c-1249.47,-518.75) -1163.44,-360.9 cw(c-1253.08,-524.83) -1129.72,-384.51 cw(c-1257.58,-530.13) -1101.79,-414.88 cw(c-1255.3,-528.61) -1080.93,-450.53 cw(c-1246.12,-524.56) -1068.44,-489.95 cw(c-1252.71,-525.55) -1065.12,-531.22 cw(c-1259.91,-525.46) -1070.76,-572.34 cw(c-1257.49,-526.19) -1085.02,-611.35 cw(c-1248.49,-530.71) -1107.55,-646.31 cw(c-1253.11,-526.51) -1137.41,-675.35 cw(c-1257.77,-520.72) -1172.89,-697.33 cw(c-1256.89,-522.85) -1212.28,-711.29 cw(c-1254.64,-532.68) -1253.81,-716.24 cw(c-1254.32,-526.9) -1295.46,-711.72 cw(c-1252.78,-519.38) -1335.25,-698.31 cw(c-1253.77,-521.21) -1371.31,-676.73 cw(c-1259.91,-529.21) -1401.78,-647.72 cw(c-1255.6,-526.09) -1424.98,-612.55 cw(c-1248.6,-522.38) -1440.08,-573.12 cw(c-1250.43,-522.72) -1446.48,-531.34 cw(c-1260.49,-523.08) -1443.54,-489.13 cw(c-1255.83,-524.34) -1431.15,-448.6 cw(c-1248.28,-527.47) -1410.27,-411.62 cw(c-1249.53,-526.41) -1381.99,-379.89 cw(c-1256.18,-518.91) -1347.4,-355.1 cw(c-1254.46,-522.87) -1308.06,-338.72 cw(c-1251.99,-530.9) -1266.01,-331.2 cw(c-1251.95,-529.5) -1223.29,-332.77 cw(c-1250.42,-519.65) -1181.91,-343.68 cw(c-1252.2,-523) -1143.99,-363.66 cw(c-1256.95,-530.22) -1111.22,-391.43 cw(c-1256.01,-529.52) -1085.06,-425.55 cw(c-1247.5,-524.46) -1066.98,-464.6 cw(c-1250.7,-525.04) -1058.16,-506.79 cw(c-1259.53,-526) -1058.67,-549.98 cw(c-1258.63,-526.25) -1068.35,-592.12 cw(c-1249.38,-529.56) -1087.02,-631.17 cw(c-1251.38,-527.74) -1114.05,-665.05 cw(c-1257.92,-521.39) -1147.84,-692.33 cw(c-1257.67,-522.03) -1186.7,-711.84 cw(c-1254.36,-531.19) -1228.92,-722.41 cw(c-1254.15,-529.06) -1272.5,-723.18 cw(c-1253.39,-519.73) -1315.29,-714.47 cw(c-1253.66,-520.1) -1355.31,-696.87 cw(c-1258.56,-528.41) -1390.57,-670.93 cw(c-1257.17,-527.64) -1419.1,-637.67 cw(c-1249.31,-522.15) -1439.78,-598.93 cw(c-1249.53,-522.09) -1451.78,-556.63 cw(c-1258.95,-523.59) -1454.29,-512.7 cw(c-1258.07,-524.14) -1446.81,-469.27 cw(c-1248.61,-526.77) -1430.04,-428.43 cw(c-1248.47,-526.67) -1404.96,-392.02 cw(c-1255.55,-520.44) -1372.53,-361.92 cw(c-1255.78,-520.99) -1334.09,-339.88 cw(c-1251.68,-530.17) -1291.7,-326.69 cw(c-1251.47,-530.46) -1247.42,-322.8 cw(c-1251.18,-521.16) -1203.32,-328.62 cw(c-1251.59,-520.74) -1161.6,-344.27 cw(c-1256.16,-529.95) -1124.22,-368.67 cw(c-1256.42,-530.5) -1092.83,-400.49 cw(c-1249.16,-524.87) -1069.08,-438.38 cw(c-1248.54,-524.02) -1054.46,-480.72 cw(c-1258.77,-526.42) -1049.42,-525.32 cw(c-1259.62,-526.58) -1053.95,-570.03 cw(c-1250.79,-528.56) -1068.08,-612.72 cw(c-1249.18,-528.76) -1091.51,-651.18 cw(c-1257.72,-522.27) -1122.83,-683.66 cw(c-1258.55,-521.51) -1160.37,-708.79 cw(c-1254.51,-529.46) -1202.5,-725.21 cw(c-1253.49,-531.43) -1247.31,-731.71 cw(c-1253.94,-520.5) -1292.53,-728.26 cw(c-1253.84,-519.11) -1336.06,-715.27 cw(c-1257.34,-527.16) -1375.77,-693.16 cw(c-1258.57,-529.7) -1409.53,-662.62 cw(c-1250.28,-522.25) -1435.83,-625.38 cw(c-1248.92,-521.32) -1453.66,-583.33 cw(c-1257.21,-523.7) -1461.98,-538.41 cw(c-1260.57,-524.4) -1459.96,-492.69 cw(c-1249.35,-526.07) -1447.96,-448.45 cw(c-1247.51,-526.63) -1426.81,-407.7 cw(c-1254.51,-521.84) -1397.35,-372.46 cw(c-1257.59,-519.24) -1360.65,-344.73 cw(c-1251.64,-529.11) -1318.69,-325.68 cw(c-1250.81,-531.14) -1273.57,-315.96 cw(c-1251.56,-522.85) -1227.4,-316.2 cw(c-1251.44,-518.22) -1182.39,-326.85 cw(c-1255.31,-529.25) -1140.76,-347.15 cw(c-1256.49,-531.42) -1104.32,-375.87 cw(c-1250.7,-525.68) -1074.92,-411.79 cw(c-1246.54,-522.52) -1054.33,-453.47 cw(c-1257.65,-526.61) -1043.38,-498.72 cw(c-1260.35,-527.12) -1042.29,-545.35 cw(c-1252.4,-527.91) -1051.27,-591.13 cw(c-1246.75,-529.3) -1070.34,-633.79 cw(c-1257.1,-523.28) -1098.39,-671.27 cw(c-1259.42,-521.33) -1133.8,-701.98 cw(c-1255.07,-527.82) -1175.02,-724.36 cw(c-1252.34,-533.6) -1220.28,-736.92 cw(c-1254.31,-521.67) -1267.27,-739.21 cw(c-1254.27,-518.36) -1313.75,-731.45 cw(c-1256.45,-525.68) -1357.49,-713.87 cw(c-1259.45,-531.94) -1396.22,-686.87 cw(c-1251.45,-522.75) -1428.09,-651.94 cw(c-1251.39,-522.1) -1466.26,-565.83 cw(c-1262.79,-525.18) -1470.18,-518.54 cw(c-1250.54,-525.5) -1463.54,-471.48 cw(c-1249.62,-525.24) -1421.3,-386.75 cw(c-1259.57,-518.11) -1387.19,-353.41 cw(c-1252,-527.8) -1346.49,-328.4 cw(c-1251.05,-528.7) -1253.81,-306.84 cw(c-1251.87,-516.06) -1206.14,-311.89 cw(c-1254.52,-528.09) -1160.7,-327.39 cw(c-1254.79,-529.75) -1084.63,-385.36 cw(c-1245.25,-520.84) -1057.99,-425.51 cw(c-1256.21,-526.45) -1040.89,-470.63 cw(c-1258.05,-527.39) -1037.06,-566.68 cw(c-1244.75,-529.16) -1051.08,-613.02 cw(c-1256.01,-524.3) -1075.06,-655.17 cw(c-1258.23,-523.22) -1147,-719.65 cw(c-1250.98,-534.92) -1191.86,-738.5 cw(c-1254.37,-523.21) -1239.86,-746.92 cw(c-1254.97,-520.4) -1335.87,-732.52 cw(c-1256.81,-528.57) -1416.47,-678.08 cw(c-1250.61,-521.22) -1466.82,-594.5 cw(c-1258.51,-525.09) -1476.31,-497.23 cw(c-1248.46,-525.25) -1443.83,-404.71 cw(c-1256.81,-521.36) -1374.59,-335.05 cw(c-1250.31,-529.57) -1282.14,-300.94 cw(c-1252.64,-520.23) -1183.86,-309.93 cw(c-1254.96,-530.86) -1098.24,-359.67 cw(c-1248.92,-522.85) -1042.24,-441.52 cw(c-1258.98,-527.97) -1025.93,-539.67 cw(c-1248.56,-527.61) -1053.42,-635.46 cw(c-1259.26,-522.91) -1118.98,-710.95 cw(c-1249.95,-534.87) -1162.56,-736.17 cw(c-1254,-525.06) -1210.74,-751.02 cw(c-1255.41,-519.44) -1311.18,-748.6 cw(c-1258.73,-534.29) -1358.62,-731.02 cw(c-1253.9,-525.26) -1400.97,-703.23 cw(c-1250.18,-520.27) -1463.42,-623.91 cw(c-1263.78,-527.17) -1480.2,-575.93 cw(c-1254.13,-525.25) -1485.81,-525.34 cw(c-1247.49,-524.95) -1464.38,-426.2 cw(c-1261.45,-518.85) -1437.99,-382.47 cw(c-1254.2,-524.82) -1402.42,-345.73 cw(c-1249.47,-530.09) -1311.94,-298.83 cw(c-1253.63,-515.47) -1261.18,-291.25 cw(c-1253.65,-524.39) -1209.96,-295.25 cw(c-1255.1,-532.8) -1160.7,-310.19 cw(c-1253.56,-529.59) -1115.71,-335.28 cw(c-1246.21,-519.36) -1077.33,-369.71 cw(c-1252.73,-524.66) -1047.63,-411.93 cw(c-1260.39,-529.05) -1027.65,-459.63 cw(c-1257.2,-528.27) -1018.27,-510.53 cw(c-1244.59,-527.42) -1020.33,-562.29 cw(c-1252.3,-525.83) -1033.99,-612.32 cw(c-1260.84,-522.61) -1058.14,-658.33 cw(c-1258.43,-524.43) -1091.53,-698.18 cw(c-1249.74,-533.61) -1132.92,-729.74 cw(c-1253.11,-527.12) -1180.39,-751.2 cw(c-1256.17,-518.22) -1231.47,-761.97 cw(c-1256.06,-520.95) -1283.71,-761.64 cw(c-1257.6,-533.49) -1334.64,-749.82 cw(c-1254.92,-527.32) -1381.66,-726.81 cw(c-1249.85,-519.05) -1422.69,-694.16 cw(c-1251.69,-520.67) -1455.88,-653.51 cw(c-1262.31,-527.45) -1479.36,-606.52 cw(c-1256.41,-525.82) -1491.66,-555.39 cw(c-1246.52,-524.42) -1492.66,-502.72 cw(c-1248.66,-524.06) -1482.44,-450.99 cw(c-1260.6,-520.21) -1461.1,-402.73 cw(c-1256.14,-523.41) -1429.41,-360.47 cw(c-1248.55,-530.34) -1389.27,-325.97 cw(c-1249.47,-528.7) -1342.68,-300.77 cw(c-1254.08,-517.11) -1291.67,-286.37 cw(c-1253.84,-521.95) -1238.66,-283.84 cw(c-1254.36,-532.49) -1186.26,-292.83 cw(c-1253.76,-531.03) -1136.92,-312.75 cw(c-1247.81,-520.16) -1093.1,-343.02 cw(c-1250.95,-522.91) -1057.2,-382.42 cw(c-1259.64,-529.4) -1030.61,-428.74 cw(c-1258.4,-529.04) -1014.45,-479.69 cw(c-1246.34,-526.73) -1009.81,-532.98 cw(c-1249.76,-526.06) -1017.31,-586 cw(c-1260.57,-523.43) -1036.15,-636.24 cw(c-1259.78,-524.02) -1065.24,-681.37 cw(c-1250.41,-531.77) -1103.51,-719.09 cw(c-1251.62,-529.25) -1149.35,-747.23 cw(c-1256.6,-518.99) -1200.3,-764.81 cw(c-1256.63,-519.68) -1253.86,-771.18 cw(c-1256.62,-531.71) -1307.55,-765.72 cw(c-1255.6,-529.88) -1358.69,-748.26 cw(c-1250.75,-519.25) -1404.91,-720.08 cw(c-1251.11,-519.43) -1444.13,-682.7 cw(c-1260.27,-527.01) -1474.29,-637.65 cw(c-1258.85,-526.97) -1493.53,-586.9 cw(c-1247.3,-523.87) -1501.3,-533.08 cw(c-1247.36,-523.69) -1497.47,-478.79 cw(c-1258.89,-521.49) -1481.92,-426.6 cw(c-1258.65,-522.27) -1454.96,-379.22 cw(c-1248.67,-529.35) -1418.28,-338.75 cw(c-1248.36,-529.43) -1373.81,-306.96 cw(c-1253.93,-519.28) -1323.47,-285.58 cw(c-1254.59,-519.24) -1269.53,-276.1 cw(c-1253.68,-531.71) -1214.73,-278.59 cw(c-1253.59,-532.31) -1161.66,-292.66 cw(c-1249.37,-521.71) -1112.88,-317.93 ; v3(-1252,-498) v3@-1241.76,-498 ; v3(-1237,-503) -1214.69,-525.31 ; -1112.88,-317.92 cw(c-1249.34,-520.55) -1071,-353.59 cw(c-1258.57,-529.38) -1037.85,-397.6 cw(c-1259.24,-530) -1014.77,-447.69 cw(c-1248.54,-526.55) -1003.09,-501.61 cw(c-1246.88,-525.76) -1003.87,-556.85 cw(c-1259.82,-524.25) -1016.71,-610.68 cw(c-1261.03,-524.02) -1040.7,-660.61 cw(c-1251.7,-529.97) -1074.96,-704.18 cw(c-1249.51,-531.29) -1118.21,-738.94 cw(c-1256.72,-520.14) -1168.08,-763.46 cw(c-1257.43,-518.75) -1222.09,-776.85 cw(c-1256.09,-529.56) -1277.73,-778.24 cw(c-1255.79,-532.85) -1332.32,-767.03 cw(c-1251.73,-519.95) -1383.22,-744.12 cw(c-1250.94,-518.24) -1428.15,-710.89 cw(c-1258.29,-526.01) -1464.85,-668.73 cw(c-1261.26,-528.75) -1491.13,-619.31 cw(c-1248.52,-523.58) -1505.98,-565.25 cw(c-1246.37,-523.05) -1509.03,-509.21 cw(c-1256.85,-522.35) -1499.89,-453.82 cw(c-1261.57,-521.58) -1478.48,-401.84 cw(c-1249.28,-528.21) -1446.16,-355.75 cw(c-1247.25,-529.74) -1404.73,-317.52 cw(c-1253.27,-521.38) -1356.02,-289.13 cw(c-1255.96,-516.57) -1302.09,-272.41 cw(c-1253.21,-530.46) -1245.74,-267.93 cw(c-1253.1,-533.33) -1189.63,-275.52 cw(c-1250.54,-523.57) -1136.48,-295.03 cw(c-1248.2,-517.79) -1089.02,-326.05 cw(c-1257.27,-528.9) -1049.48,-366.8 cw(c-1259.67,-531.02) -1019.45,-415.08 cw(c-1250.71,-526.87) -1000.52,-468.7 cw(c-1244.06,-524.85) -994.13,-525.28 cw(c-1258.56,-524.94) -1000.35,-581.96 cw(c-1262.06,-524.36) -1018.5,-636.1 cw(c-1253.35,-528.53) -1047.87,-685.07 cw(c-1247.02,-532.81) -1087.56,-726.24 cw(c-1256.4,-521.59) -1135.4,-757.7 cw(c-1258.34,-518.23) -1188.91,-778.31 cw(c-1256.07,-527.38) -1245.61,-786.93 cw(c-1255.34,-535.67) -1302.87,-782.59 cw(c-1252.64,-521.18) -1357.83,-765.7 cw(c-1251.15,-517.23) -1408.02,-737.48 cw(c-1256.62,-524.63) -1450.99,-699.13 cw(c-1263.06,-530.89) -1484.29,-652.05 cw(c-1250.1,-523.7) -1506.4,-598.71 cw(c-1249.51,-522.91) -1514.51,-484.01 cw(c-1264.28,-521.63) -1499.41,-428.11 cw(c-1250.44,-527.05) -1472.29,-376.86 cw(c-1249.07,-527.28) -1388.72,-297.18 cw(c-1257.72,-514.63) -1335.81,-273.07 cw(c-1253.08,-528.77) -1278.8,-261.25 cw(c-1252.35,-530.46) -1163.65,-274.92 cw(c-1247.91,-515.3) -1111.13,-300.42 cw(c-1255.86,-527.86) -1065.5,-336.97 cw(c-1257.05,-529.83) -1002.38,-434.81 cw(c-1242.11,-523.48) -988.48,-491.77 cw(c-1256.81,-525.34) -987.56,-550.46 cw(c-1259.57,-525.61) -1022.86,-661.92 cw(c-1244.82,-533.33) -1058.03,-709.14 cw(c-1255.54,-523.23) -1102.85,-747.41 cw(c-1257.78,-520.86) -1211.69,-791.43 cw(c-1254.66,-530.48) -1329.03,-784.27 cw(c-1252.79,-519.25) -1432.73,-728.22 cw(c-1258.61,-528.13) -1502.3,-632.87 cw(c-1248.28,-522.22) -1525.3,-516.76 cw(c-1259.34,-523.32) -1496.07,-401.91 cw(c-1247.76,-527.75) -1420.95,-309.81 cw(c-1255.91,-519.49) -1313.39,-258.92 cw(c-1251.86,-531.73) -1194.06,-258.1 cw(c-1250.52,-519.72) -1085.86,-308.73 cw(c-1257.67,-531.01) -1008.86,-400.53 cw(c-1247.11,-524.24) -978.77,-516.64 cw(c-1260.84,-525.92) -1000.53,-634.95 cw(c-1248.49,-529.99) -1071.08,-732.54 cw(c-1258.82,-520.12) -1176.54,-791.41 cw(c-1253.15,-537.61) -1236.38,-802.19 cw(c-1253.68,-525.22) -1297.18,-799.3 cw(c-1252.92,-518) -1410.21,-755.38 cw(c-1262.82,-533.53) -1456.85,-715.99 cw(c-1253.95,-525.58) -1493.52,-667.11 cw(c-1247.45,-521.32) -1531.87,-551.56 cw(c-1265.72,-523.56) -1531.26,-490.28 cw(c-1254.47,-525.3) -1516.91,-430.63 cw(c-1246.57,-527.79) -1452.05,-327.03 cw(c-1259.88,-515.14) -1404.26,-288.27 cw(c-1254.39,-524.46) -1348.94,-261.2 cw(c-1250.8,-533.89) -1289,-246.61 cw(c-1251.19,-529.5) -1227.29,-245.09 cw(c-1249.83,-514.39) -1166.73,-257.25 cw(c-1253.37,-523.98) -1110.39,-282.71 cw(c-1258.52,-533.05) -1060.74,-319.75 cw(c-1255.6,-530.19) -1020.09,-366.52 cw(c-1243.06,-521.59) -990.73,-421.14 cw(c-1252.12,-524.71) -974.37,-481.02 cw(c-1262.73,-526.57) -971.27,-543.12 cw(c-1259,-526.98) -981.43,-604.49 cw(c-1244.38,-531.18) -1004.88,-662.16 cw(c-1251.94,-526.48) -1040.73,-713.13 cw(c-1260.39,-519.26) -1086.78,-755.26 cw(c-1258.54,-522.12) -1140.77,-786.66 cw(c-1252.46,-536.05) -1200.38,-805.44 cw(c-1253.5,-527.91) -1262.74,-810.32 cw(c-1253.31,-516.46) -1324.8,-801.65 cw(c-1254.25,-519.39) -1383.63,-779.99 cw(c-1261.1,-532.9) -1436.3,-745.9 cw(c-1255.92,-527.5) -1479.98,-700.79 cw(c-1246.71,-520.14) -1512.98,-647.24 cw(c-1249.26,-521.13) -1533.86,-587.87 cw(c-1263.97,-524.45) -1541.21,-525.32 cw(c-1257.26,-525.03) -1534.27,-462.66 cw(c-1245.4,-527.51) -1513.95,-402.88 cw(c-1247.47,-526.32) -1481.38,-348.74 cw(c-1259.33,-517.15) -1437.71,-303.03 cw(c-1256.02,-522.11) -1384.82,-268.3 cw(c-1250.22,-533.13) -1325.57,-245.77 cw(c-1250.54,-531.11) -1262.85,-236.33 cw(c-1251.02,-516.25) -1199.56,-240.84 cw(c-1252.6,-521.16) -1138.85,-259.53 cw(c-1257.53,-532.95) -1083.52,-290.95 cw(c-1256.39,-531.72) -1036.09,-333.42 cw(c-1245.33,-521.96) -999.07,-385.26 cw(c-1249.42,-523.45) -974.68,-444.17 cw(c-1261.96,-527.25) -963.59,-507.07 cw(c-1260.64,-527.37) -966.1,-570.93 cw(c-1246.23,-529.66) -982.5,-632.73 cw(c-1249.19,-527.74) -1012.45,-689.3 cw(c-1260.38,-520.32) -1054.01,-738.11 cw(c-1259.88,-521.15) -1105.01,-777.03 cw(c-1252.54,-533.58) -1163.3,-803.89 cw(c-1252.67,-530.89) -1226.21,-816.92 cw(c-1254.11,-517.21) -1290.55,-816 cw(c-1254.39,-517.76) -1353.28,-801.45 cw(c-1259.23,-531.17) -1411.36,-773.56 cw(c-1257.69,-530.1) -1461.69,-733.25 cw(c-1247.85,-520.05) -1502.14,-682.89 cw(c-1248.14,-519.98) -1531.01,-625.06 cw(c-1261.38,-524.73) -1546.61,-562.3 cw(c-1260.45,-525.36) -1547.64,-497.58 cw(c-1246.12,-526.57) -1534.57,-434.08 cw(c-1245.9,-526.41) -1508.3,-374.75 cw(c-1257.83,-519.33) -1469.75,-322.54 cw(c-1258.37,-519.84) -1420.37,-280.32 cw(c-1249.99,-531.92) -1362.89,-249.81 cw(c-1249.59,-532.34) -1300.19,-232.18 cw(c-1251.7,-518.83) -1235.15,-228.58 cw(c-1252.38,-517.85) -1170.9,-239.76 cw(c-1256.44,-532.3) -1110.54,-264.7 cw(c-1256.69,-533.2) -1056.79,-301.91 cw(c-1247.76,-523.13) -1012.39,-349.9 cw(c-1246.71,-521.45) -979.92,-406.74 cw(c-1260.7,-527.65) -960.6,-469.38 cw(c-1261.93,-528.11) -955,-534.76 cw(c-1248.7,-528.57) -963.7,-599.8 cw(c-1245.86,-528.54) -986.88,-661.28 cw(c-1259.82,-521.57) -1022.97,-716.29 cw(c-1261.26,-520.68) -1069.95,-762.44 cw(c-1253.32,-530.99) -1125.82,-797.33 cw(c-1251.11,-533.97) -1188.19,-818.74 cw(c-1254.7,-518.5) -1253.82,-826.02 cw(c-1254.93,-516.44) -1319.56,-819.2 cw(c-1257.77,-528.91) -1382.29,-798.32 cw(c-1259.05,-533.3) -1438.76,-763.8 cw(c-1249.26,-520.47) -1486.37,-717.7 cw(c-1247.51,-518.74) -1523.15,-662.48 cw(c-1258.72,-524.38) -1547.13,-600.62 cw(c-1263.79,-526.39) -1556.57,-534.87 cw(c-1247.41,-525.76) -1551.37,-468.56 cw(c-1244.58,-526.07) -1532.19,-404.79 cw(c-1255.84,-521.12) -1499.7,-346.67 cw(c-1261.32,-517.97) -1454.89,-297.3 cw(c-1250.24,-530.36) -1400.29,-258.91 cw(c-1248.49,-533.09) -1338.7,-232.95 cw(c-1251.78,-521.49) -1272.97,-220.89 cw(c-1252.87,-514.41) -1206.12,-223.94 cw(c-1255.4,-531.04) -1141.51,-241.62 cw(c-1256.52,-534.49) -1082.04,-272.65 cw(c-1249.83,-524.79) -1030.66,-315.76 cw(c-1244.43,-518.87) -990.25,-369.4 cw(c-1259.02,-527.61) -962.59,-430.67 cw(c-1262.77,-529.07) -948.55,-496.51 cw(c-1251.29,-528.07) -949.02,-563.83 cw(c-1242.47,-528.59) -964.63,-629.39 cw(c-1258.65,-522.86) -994.33,-689.98 cw(c-1262.5,-520.69) -1036.27,-742.94 cw(c-1254.61,-528.71) -1088.62,-785.64 cw(c-1248.99,-536.53) -1149.3,-815.52 cw(c-1254.91,-520.29) -1215.15,-831.31 cw(c-1255.74,-515.54) -1282.93,-832.74 cw(c-1256.87,-526.46) -1349.44,-819.58 cw(c-1259.59,-536.51) -1411.37,-791.79 cw(c-1250.79,-521.52) -1465.7,-750.97 cw(c-1250.83,-520.53) -1542.53,-639.61 cw(c-1266.48,-528.04) -1560.66,-573.95 cw(c-1249.26,-525.27) -1563.84,-505.83 cw(c-1247.96,-524.66) -1526.88,-375.18 cw(c-1264.22,-517.06) -1487.71,-319.15 cw(c-1251.1,-528.59) -1437.07,-273.12 cw(c-1249.49,-529.67) -1312.4,-218.14 cw(c-1254.06,-511.74) -1244.02,-212.57 cw(c-1254.59,-529.17) -1176.04,-222.29 cw(c-1254.55,-531.66) -1053.78,-283.54 cw(c-1244.61,-517.81) -1005.7,-332.82 cw(c-1257.3,-527.77) -969.62,-391.57 -968.95,-391.91 cw(c-1261.54,-530.69) -943.92,-467.51 ; -943.38,-468.62 v2(-909,-503)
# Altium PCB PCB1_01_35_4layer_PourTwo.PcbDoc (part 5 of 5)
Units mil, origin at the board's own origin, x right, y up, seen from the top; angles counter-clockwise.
Board outline 1043.31 x 669.29 mil, 4 copper layers (Top Layer, Layer 1, Layer 2, Bottom Layer), stack 23.756 mil thick; 0 components, 1 nets, 8 pads, 85 vias.

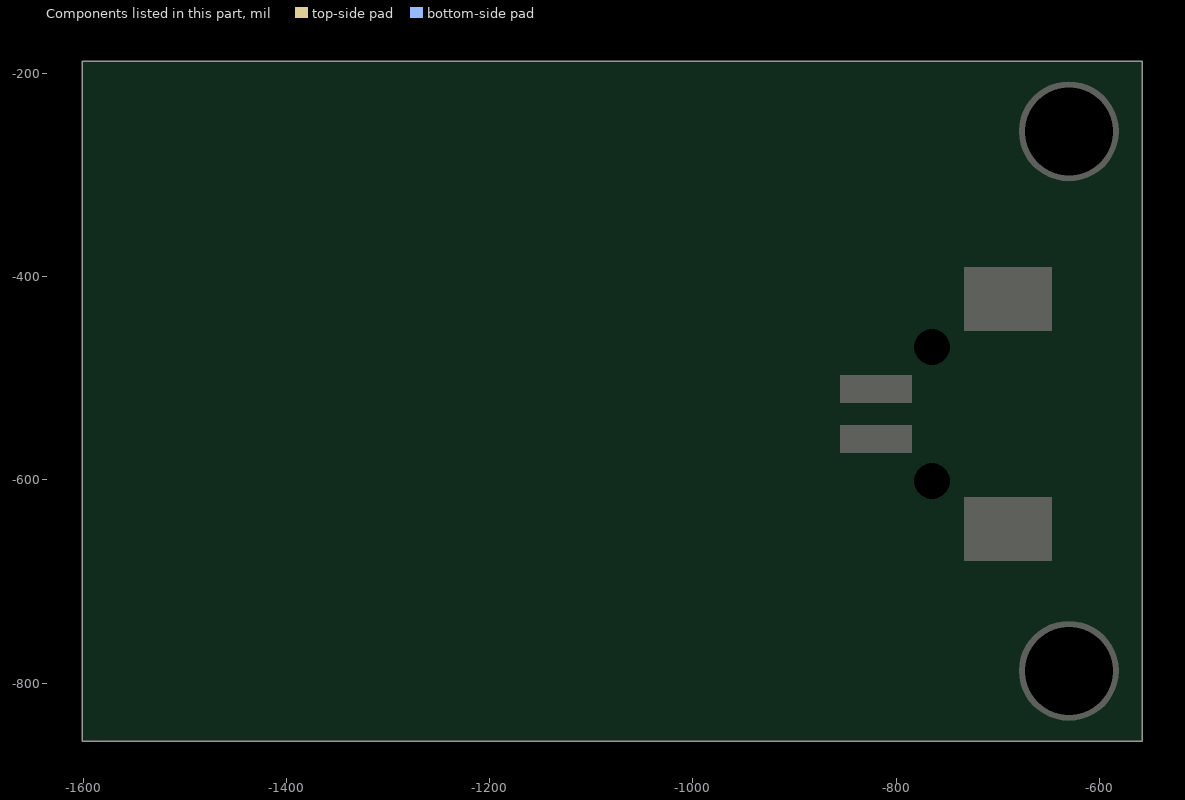
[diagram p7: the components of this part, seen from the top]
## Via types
v1: diameter 19.68, hole 11.81, Top Layer to Bottom Layer, tented both sides, 70 vias
v2: diameter 39.37, hole 19.68, Top Layer to Bottom Layer, 9 vias
v3: diameter 19.68, hole 11.81, Top Layer to Bottom Layer, 6 vias

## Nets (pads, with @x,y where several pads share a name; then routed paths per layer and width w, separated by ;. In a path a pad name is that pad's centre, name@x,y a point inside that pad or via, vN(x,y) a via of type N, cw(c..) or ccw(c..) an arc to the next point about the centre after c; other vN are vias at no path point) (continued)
copper on no net: (continued)
  Bottom Layer w3.94: v3(-1267,-502) -1292.55,-527.55 -1293.74,-527.55 ccw(c-1253.77,-522.46) -1291.42,-536.82 ccw(c-1250.16,-521.1) -1287.04,-545.37 ccw(c-1247.94,-519.67) -1280.9,-552.88 ccw(c-1247.83,-519.61) -1273.32,-558.99 ccw(c-1249,-521.47) -1264.59,-563.38 ccw(c-1250.05,-524.31) -1255.02,-565.7 ccw(c-1250.04,-523.1) -1245.11,-565.7 ccw(c-1250.46,-519.28) -1235.38,-563.51 ccw(c-1251.09,-517.33) -1226.24,-559.31 ccw(c-1250.72,-517.88) -1218.14,-553.29 ccw(c-1248.85,-519.89) -1211.5,-545.65 ccw(c-1247.61,-520.94) -1204.23,-526.65 ccw(c-1252.98,-519.96) -1203.91,-516.3 ccw(c-1253.74,-519.92) -1209.67,-496.37 ccw(c-1250.16,-518.09) -1215.65,-487.76 ccw(c-1248.83,-517.02) -1223.55,-480.72 ccw(c-1251.18,-520.4) -1232.89,-475.64 ccw(c-1252.42,-523.34) -1243.18,-472.63 ccw(c-1252.55,-523.84) -1253.91,-471.8 ccw(c-1252.64,-521.65) -1264.61,-473.24 ccw(c-1253.46,-518.36) -1274.78,-477.07 ccw(c-1253.19,-518.55) -1283.83,-483.21 ccw(c-1250.39,-521.82) -1291.32,-491.27 ccw(c-1248.33,-523.4) -1297,-500.78 ccw(c-1248.67,-523.29) -1300.62,-511.3 ccw(c-1251.44,-522.68) -1301.91,-522.38 ccw(c-1254.84,-522.65) -1300.64,-533.54 ccw(c-1252.43,-521.96) -1296.77,-544.15 ccw(c-1248.72,-520.14) -1290.64,-553.72 ccw(c-1247.57,-519.33) -1273.04,-568.21 ccw(c-1249.54,-522.99) -1262.29,-572.33 ccw(c-1250.26,-525.56) -1250.79,-573.85 ccw(c-1250.24,-521.41) -1239.19,-572.67 ccw(c-1250.99,-517.73) -1228.04,-569.02 ccw(c-1251.36,-516.81) -1217.81,-563.12 ccw(c-1250.1,-518.49) -1209.03,-555.21 ccw(c-1247.32,-520.95) -1202.19,-545.5 ccw(c-1246.7,-521.45) -1197.79,-534.37 ccw(c-1251.25,-520.23) -1195.99,-522.49 ccw(c-1254.43,-520.06) -1196.75,-510.4 ccw(c-1254.47,-520.03) -1199.98,-498.69 ccw(c-1251.82,-518.95) -1205.63,-487.9 ccw(c-1248.61,-516.79) -1213.62,-478.61 ccw(c-1249.61,-518.12) -1223.62,-471.42 ccw(c-1251.9,-522.16) -1235.02,-466.57 ccw(c-1252.64,-524.47) -1247.26,-464.19 ccw(c-1252.6,-523.53) -1259.77,-464.38 ccw(c-1253.05,-520.06) -1271.97,-467.27 ccw(c-1253.49,-518.17) -1292.95,-481.08 ccw(c-1248.91,-522.92) -1300.72,-491.21 ccw(c-1248.33,-523.42) -1309.29,-515.27 ccw(c-1253.39,-522.66) -1309.51,-528.17 ccw(c-1255.35,-522.74) -1306.68,-540.85 ccw(c-1250.65,-521.08) -1301.02,-552.59 ccw(c-1247.42,-519.11) -1292.94,-562.95 ccw(c-1247.01,-518.79) -1282.87,-571.45 ccw(c-1248.55,-521.12) -1271.21,-577.67 ccw(c-1250.12,-525.06) -1258.4,-581.13 ccw(c-1250.23,-524.49) -1245.06,-581.48 ccw(c-1250.67,-519.38) -1231.91,-578.85 ccw(c-1251.54,-516.46) -1219.53,-573.49 ccw(c-1251.22,-516.92) -1208.47,-565.68 ccw(c-1248.85,-519.58) -1199.32,-555.67 ccw(c-1245.47,-522.05) -1192.66,-543.76 ccw(c-1248.47,-520.95) -1188.95,-530.57 ccw(c-1253.29,-520.14) -1188.2,-516.81 ccw(c-1254.82,-520.1) -1195.23,-490.13 ccw(c-1250.15,-517.84) -1202.86,-478.49 ccw(c-1247.7,-515.89) -1213.07,-468.88 ccw(c-1250.66,-519.94) -1225.25,-461.86 ccw(c-1252.46,-523.97) -1238.73,-457.56 ccw(c-1252.73,-525) -1252.88,-456.12 ccw(c-1252.78,-522.36) -1267.03,-457.67 ccw(c-1253.78,-517.91) -1280.53,-462.34 ccw(c-1253.94,-517.16) -1292.63,-470.09 ccw(c-1250.42,-521.47) -1302.72,-480.41 ccw(c-1247.55,-523.79) -1310.47,-492.69 ccw(c-1247.64,-523.8) -1315.54,-506.35 ccw(c-1251.07,-522.96) -1317.61,-520.78 ccw(c-1255.78,-522.81) -1316.35,-535.4 ccw(c-1253.68,-522.19) -1311.68,-549.36 ccw(c-1248.74,-519.91) -1304.01,-562.02 ccw(c-1246.5,-518.27) -1293.83,-572.88 ccw(c-1247.28,-519.25) -1281.6,-581.42 ccw(c-1249.32,-523.01) -1267.8,-587.14 ccw(c-1250.18,-525.01) -1237.91,-588.41 ccw(c-1251.28,-517.35) -1223.37,-584.05 ccw(c-1251.41,-516.63) -1198.39,-566.83 ccw(c-1246.97,-520.99) -1189.23,-554.57 ccw(c-1245.19,-522.2) -1183.16,-540.42 ccw(c-1250.81,-520.54) -1180.45,-525.21 ccw(c-1255.16,-520.2) -1181.03,-509.67 ccw(c-1255.64,-520.21) -1184.8,-494.53 ccw(c-1252.44,-519.01) -1191.67,-480.52 ccw(c-1248.14,-516.26) -1201.56,-468.34 ccw(c-1248.6,-517.05) -1214.08,-458.79 ccw(c-1251.66,-522.16) -1228.48,-452.23 ccw(c-1252.8,-525.43) -1244.02,-448.79 ccw(c-1252.77,-524.65) -1259.97,-448.63 ccw(c-1253.21,-520.36) -1275.6,-451.88 ccw(c-1254.74,-515.66) -1290.16,-458.66 ccw(c-1252.55,-518.93) -1302.76,-468.68 ccw(c-1248.59,-522.95) -1312.95,-481.27 ccw(c-1247.33,-523.93) -1324.61,-511.5 ccw(c-1253.48,-522.85) -1325.34,-527.8 ccw(c-1257,-522.99) -1322.23,-543.93 ccw(c-1251.39,-521.17) -1315.48,-558.96 ccw(c-1247.02,-518.65) -1305.63,-572.28 ccw(c-1246.16,-517.95) -1293.21,-583.34 ccw(c-1247.99,-520.57) -1278.74,-591.56 ccw(c-1250.13,-525.55) -1262.75,-596.37 ccw(c-1250.45,-526.14) -1245.99,-597.3 ccw(c-1250.83,-519.73) -1229.4,-594.44 ccw(c-1251.93,-515.69) -1213.68,-588.13 ccw(c-1251.77,-515.86) -1199.57,-578.69 ccw(c-1249.02,-519.09) -1187.76,-566.47 ccw(c-1244.64,-522.48) -1178.99,-551.81 ccw(c-1247.26,-521.52) -1173.88,-535.46 ccw(c-1253.37,-520.32) -1172.48,-518.3 ccw(c-1255.95,-520.28) -1180.38,-484.78 ccw(c-1250.36,-517.73) -1189.48,-470.01 ccw(c-1248.32,-516.56) -1216.72,-448.51 ccw(c-1252.46,-524.41) -1233.33,-442.73 ccw(c-1252.78,-524.97) -1268.47,-441.93 ccw(c-1254.01,-517.72) -1285.37,-447.23 ccw(c-1253.93,-517.28) -1300.68,-456.37 ccw(c-1250.31,-522.06) -1313.63,-468.73 ccw(c-1248.63,-523.63) -1330.45,-500.32 ccw(c-1254.35,-521.92) -1333.37,-518.15 ccw(c-1253.97,-521.7) -1332.11,-536.24 ccw(c-1248.47,-520.72) -1326.89,-553.68 ccw(c-1247.54,-520.52) -1306.08,-583.52 ccw(c-1252.23,-525.37) -1291.24,-594.36 ccw(c-1250.99,-522.8) -1274.27,-601.53 ccw(c-1249.49,-517.91) -1256.06,-604.88 ccw(c-1249.35,-516.9) -1237.49,-604.33 ccw(c-1248.84,-520.29) -1219.44,-599.84 ccw(c-1248.05,-523.16) -1188.47,-579.27 ccw(c-1253.13,-517.82) -1177.02,-564.34 ccw(c-1253.1,-517.76) -1168.92,-547.29 ccw(c-1249.12,-519.11) -1164.68,-528.87 ccw(c-1245.38,-519.64) -1164.74,-509.89 ccw(c-1251.37,-520.37) -1169.07,-491.35 ccw(c-1254.9,-521.55) -1177.28,-474.07 ccw(c-1254.07,-520.96) -1188.96,-458.87 ccw(c-1250.58,-517.57) -1203.69,-446.55 ccw(c-1249.51,-516.34) -1220.92,-437.9 ccw(c-1251.68,-522.18) -1239.71,-433.27 ccw(c-1252.1,-524.25) -1278.27,-436.23 ccw(c-1253.92,-517.81) -1296.2,-443.92 ccw(c-1253.19,-518.58) -1311.95,-455.56 ccw(c-1249.21,-522.91) -1324.82,-470.42 ccw(c-1248.82,-523.43) -1339.95,-506.64 ccw(c-1256.07,-521.93) -1341.21,-526.43 ccw(c-1252.46,-521.56) -1337.91,-546.03 ccw(c-1247.32,-520.15) -1330.42,-564.54 ccw(c-1246.57,-519.82) -1319.19,-581.12 ccw(c-1249.52,-522.38) -1304.65,-594.93 ccw(c-1251.42,-524.35) -1268.05,-611.18 ccw(c-1249.52,-516.8) -1247.85,-612.97 ccw(c-1249.45,-517.06) -1227.69,-610.48 ccw(c-1248.33,-521.64) -1208.5,-603.69 ccw(c-1246.89,-524.92) -1191.3,-592.66 ccw(c-1251.05,-519.84) -1176.97,-578.01 ccw(c-1253.96,-517.47) -1166.02,-560.59 ccw(c-1252.7,-518.01) -1158.96,-541.22 ccw(c-1247.46,-519.26) -1156.28,-520.74 ccw(c-1246.38,-519.53) -1158.39,-500.12 ccw(c-1252.82,-520.9) -1165.02,-480.4 ccw(c-1254.58,-521.53) -1189.93,-447.15 ccw(c-1249.61,-516) -1207.25,-435.33 ccw(c-1250.21,-517.7) -1226.87,-427.78 ccw(c-1251.81,-523.63) -1247.75,-424.67 ccw(c-1251.95,-525.34) -1268.89,-426.01 ccw(c-1252.6,-521.93) -1289.28,-431.82 ccw(c-1254.88,-516.35) -1307.91,-442.08 ccw(c-1252.16,-519.88) -1323.76,-456.36 ccw(c-1248.08,-523.57) -1336.21,-473.79 ccw(c-1247.61,-523.93) -1344.75,-493.49 ccw(c-1251.84,-522.66) -1348.89,-514.58 ccw(c-1254.16,-522.07) -1342.51,-557.04 ccw(c-1246.41,-519.52) -1332.53,-576.33 ccw(c-1246.85,-519.9) -1318.69,-593.14 ccw(c-1250.48,-523.67) -1301.52,-606.57 ccw(c-1252.35,-526.36) -1281.67,-615.76 ccw(c-1250.13,-519.66) -1260.2,-620.3 ccw(c-1249.68,-515.93) -1238.17,-620.2 ccw(c-1249.42,-517.67) -1216.63,-615.46 ccw(c-1247.49,-523.27) -1196.6,-606.11 ccw(c-1247.49,-523.8) -1179.2,-592.36 ccw(c-1252.34,-518.87) -1165.2,-575.06 ccw(c-1253.54,-517.86) -1149.47,-533.51 ccw(c-1245.48,-519.22) -1148.75,-511.1 ccw(c-1248.06,-519.69) -1153.2,-489.07 ccw(c-1254.14,-521.6) -1162.36,-468.46 ccw(c-1255.51,-522.29) -1175.68,-450.17 ccw(c-1252.61,-519.59) -1192.6,-435.11 ccw(c-1248.93,-514.41) -1212.54,-424.21 ccw(c-1250.79,-519.38) -1234.49,-418.11 ccw(c-1251.75,-524.95) -1257.32,-416.87 ccw(c-1251.81,-525.26) -1279.96,-420.44 ccw(c-1253.15,-520.52) -1301.33,-428.8 ccw(c-1255.49,-515.86) -1320.31,-441.84 ccw(c-1250.86,-521.12) -1335.91,-458.86 ccw(c-1247.07,-523.99) -1347.57,-478.88 ccw(c-1247.95,-523.68) -1354.79,-500.95 ccw(c-1253.61,-522.53) -1357.05,-524.09 ccw(c-1256.44,-522.35) -1353.94,-547.21 ccw(c-1249.16,-520.53) -1345.76,-569.12 ccw(c-1246.43,-519.33) -1316.5,-605.55 ccw(c-1251.49,-525.4) -1296.63,-618.21 ccw(c-1251.63,-525) -1274.33,-625.98 ccw(c-1250,-517.99) -1250.78,-628.69 ccw(c-1249.77,-516.8) -1204.45,-619.1 ccw(c-1246.32,-525) -1183.92,-606.94 ccw(c-1248.65,-522.36) -1166.67,-590.36 ccw(c-1253.67,-518.11) -1153.38,-570.36 ccw(c-1254.78,-517.44) -1144.55,-547.96 ccw(c-1250.45,-518.56) -1140.69,-524.18 ccw(c-1246.4,-519.09) -1149.34,-476.88 ccw(c-1255.23,-522.36) -1161.24,-455.68 ccw(c-1255.28,-522.3) -1177.36,-437.39 ccw(c-1251.62,-518.22) -1197.04,-422.99 ccw(c-1249.01,-513.92) -1219.57,-413.41 ccw(c-1251.15,-521.25) -1243.72,-409.12 ccw(c-1251.55,-526.01) -1268.33,-410.07 ccw(c-1251.82,-524.71) -1292.23,-416.17 ccw(c-1254.07,-518.8) -1314.26,-427.33 ccw(c-1255.09,-516.77) -1333.21,-443.29 ccw(c-1249.37,-522.22) -1348.18,-463.11 ccw(c-1247.16,-523.75) -1364.19,-510.06 ccw(c-1255.76,-522.62) -1364.2,-535.07 ccw(c-1254.68,-522.17) -1358.46,-559.48 ccw(c-1247.64,-519.71) -1347.48,-582.11 ccw(c-1246.85,-519.51) -1312.55,-618.15 ccw(c-1252.33,-527.38) -1289.97,-629.6 ccw(c-1251.01,-523.12) -1265.31,-635.59 ccw(c-1250.09,-516.44) -1239.86,-636.12 ccw(c-1250.09,-515.4) -1214.79,-631.3 ccw(c-1248.56,-520.17) -1191.32,-621.23 ccw(c-1247.1,-523.57) -1153.94,-586.59 ccw(c-1254.89,-517.63) -1141.73,-563.89 ccw(c-1254.54,-517.68) -1134.53,-539.1 ccw(c-1248.6,-518.67) -1132.84,-513.31 ccw(c-1243.87,-518.63) -1137.09,-487.74 ccw(c-1251.77,-520.9) -1146.98,-463.71 ccw(c-1255.97,-523.09) -1161.79,-442.25 ccw(c-1254.71,-521.9) -1180.8,-424.35 ccw(c-1250.6,-516.38) -1203.29,-411.01 ccw(c-1249.67,-515.07) -1228.31,-403.16 ccw(c-1251.27,-523.16) -1254.52,-401.03 ccw(c-1251.42,-525.51) -1305.53,-413.36 ccw(c-1255.4,-516.91) -1327.86,-427.55 ccw(c-1253.85,-518.3) -1346.38,-446.53 ccw(c-1247.82,-523.07) -1360.37,-469.17 ccw(c-1245.91,-524.08) -1369.32,-494.3 ccw(c-1250.19,-523.13) -1372.73,-520.77 ccw(c-1257.89,-523) -1370.13,-547.41 ccw(c-1252.64,-521.64) -1361.5,-572.81 ccw(c-1246.38,-518.79) -1347.55,-595.82 ccw(c-1245.73,-518.41) -1329.05,-615.46 ccw(c-1249.3,-522.68) -1306.77,-630.68 ccw(c-1251.24,-525.27) -1254.69,-644.36 ccw(c-1250.35,-515.16) -1227.54,-642.41 ccw(c-1250.13,-515.86) -1201.36,-634.8 ccw(c-1247.57,-521.94) -1177.42,-621.69 ccw(c-1245.29,-525.57) -1157.04,-603.41 ccw(c-1251.82,-519.77) -1141.23,-580.99 ccw(c-1255.87,-517.42) -1130.48,-555.65 ccw(c-1253.75,-517.97) -1125.29,-528.59 ccw(c-1246.32,-518.53) -1126.14,-501 ccw(c-1245.51,-518.76) -1133.33,-474.28 ccw(c-1253.49,-521.86) -1146.25,-449.73 ccw(c-1255.23,-522.74) -1186.08,-411.27 ccw(c-1249.67,-514.11) -1211.35,-399.43 ccw(c-1250.33,-517.12) -1238.72,-393.69 ccw(c-1251.14,-524.96) -1266.78,-394.04 ccw(c-1251.01,-526.87) -1294.2,-400.27 ccw(c-1252.68,-522.22) -1319.69,-412.19 ccw(c-1256.85,-515.38) -1341.91,-429.59 ccw(c-1252.2,-519.82) -1359.62,-451.62 ccw(c-1246.36,-523.62) -1372.23,-477.03 ccw(c-1246.02,-523.85) -1379.24,-504.57 ccw(c-1252.11,-523.05) -1380.19,-532.99 ccw(c-1258.71,-523.45) -1374.65,-560.97 ccw(c-1250.57,-520.79) -1362.92,-587.03 ccw(c-1245.47,-517.89) -1345.85,-610.07 ccw(c-1246.25,-518.73) -1324.31,-629.05 ccw(c-1250.34,-524.63) -1299.14,-642.92 ccw(c-1252,-527.93) -1271.38,-650.69 ccw(c-1250.53,-518.87) -1242.53,-652.09 ccw(c-1250.56,-515.18) -1186.97,-636.69 ccw(c-1246.12,-523.92) -1162.95,-620.35 ccw(c-1246.51,-524.05) -1143.28,-598.89 ccw(c-1253.6,-518.82) -1128.76,-573.56 ccw(c-1254.85,-517.98) -1117.06,-516.5 ccw(c-1243.82,-518.07) -1120.82,-487.38 ccw(c-1247.74,-519.36) -1131.17,-459.85 ccw(c-1254.94,-522.95) -1147.29,-435.13 ccw(c-1256.26,-523.9) -1168.28,-414.29 ccw(c-1252.88,-519.55) -1193.23,-398.4 ccw(c-1249.23,-512.19) -1221.2,-388.5 ccw(c-1250.73,-519.44) -1250.73,-385.21 ccw(c-1250.82,-526.48) -1280.38,-388.34 ccw(c-1250.91,-526.52) -1308.77,-397.62 ccw(c-1253.74,-520.41) -1334.52,-412.8 ccw(c-1257.42,-515.25) -1356.2,-433.5 ccw(c-1250.29,-521.14) -1372.7,-458.58 ccw(c-1245.15,-523.88) -1383.53,-486.69 ccw(c-1246.71,-523.56) -1388.23,-516.48 ccw(c-1254.48,-523.24) -1386.35,-546.61 ccw(c-1257.46,-523.44) -1377.59,-575.58 ccw(c-1248.65,-519.67) -1362.59,-601.95 ccw(c-1245.84,-517.92) -1317.67,-642.54 ccw(c-1251.29,-527.07) -1289.67,-654.62 ccw(c-1251.33,-525.84) -1259.57,-659.95 ccw(c-1250.7,-516.82) -1228.95,-658.57 ccw(c-1250.54,-515.81) -1171.82,-636.84 ccw(c-1244.34,-525.81) -1148.16,-617.11 ccw(c-1248.32,-522.42) -1129.6,-592.45 ccw(c-1255.32,-518.19) -1116.77,-564.28 ccw(c-1256.51,-517.68) -1110.11,-533.98 ccw(c-1250.44,-518.27) -1110.07,-502.94 ccw(c-1245.71,-518.23) -1130.75,-444.63 ccw(c-1256.02,-524.04) -1150.19,-420.13 ccw(c-1255.81,-523.69) -1174.36,-400.21 ccw(c-1251.84,-517.52) -1202.26,-385.97 ccw(c-1249.57,-512.07) -1232.77,-378.44 ccw(c-1250.81,-521.84) -1264.24,-377.93 ccw(c-1250.38,-527.58) -1295.2,-384.13 ccw(c-1251.1,-525.62) -1324.2,-396.7 ccw(c-1255.29,-518.37) -1349.79,-415.3 ccw(c-1256.44,-516.57) -1370.48,-439.34 ccw(c-1248.26,-522.18) -1385.38,-467.42 ccw(c-1245.7,-523.48) -1396.07,-529.93 ccw(c-1257.2,-523.79) -1390.99,-561.48 ccw(c-1255.12,-522.79) -1378.8,-591.08 ccw(c-1246.99,-518.4) -1360.39,-617.37 ccw(c-1246.46,-518.39) -1309.13,-655.69 ccw(c-1251.89,-529.59) -1278.4,-665.51 ccw(c-1250.92,-523.3) -1246.19,-668.06 ccw(c-1251.1,-515.04) -1214.08,-663.6 ccw(c-1251.22,-514.12) -1183.57,-652.49 ccw(c-1248.19,-520.11) -1156.13,-635.11 ccw(c-1246.09,-523.65) -1116.24,-584.1 ccw(c-1256.79,-517.89) -1105.49,-553.19 ccw(c-1255.94,-517.97) -1101.44,-520.68 ccw(c-1247.99,-518.03) -1104.52,-488.04 ccw(c-1242.73,-517.2) -1115,-456.89 ccw(c-1252.14,-521.61) -1132.2,-428.81 ccw(c-1256.66,-524.97) -1155.03,-404.94 ccw(c-1255.06,-522.91) -1182.38,-386.38 ccw(c-1250.9,-514.96) -1213.16,-374.24 ccw(c-1250.21,-513.97) -1245.98,-369.47 ccw(c-1250.58,-524.17) -1279.11,-372.05 ccw(c-1250.43,-526.54) -1340.28,-397.63 ccw(c-1257.31,-516.29) -1365.26,-419.8 ccw(c-1254.48,-518.3) -1384.53,-447.16 ccw(c-1246.28,-522.88) -1397.42,-478.13 ccw(c-1244.09,-523.65) -1403.55,-511.2 ccw(c-1249.97,-523.29) -1402.52,-544.81 ccw(c-1259.55,-524.65) -1393.94,-577.42 ccw(c-1252.66,-521.71) -1378.15,-607.25 ccw(c-1245.73,-517.1) -1356.24,-633.07 ccw(c-1245.29,-516.81) -1329.36,-653.77 ccw(c-1249.05,-523.11) -1298.67,-668.23 ccw(c-1251.77,-530.68) -1265.41,-675.36 ccw(c-1250.87,-520.64) -1231.35,-674.82 ccw(c-1251.64,-513.68) -1198.08,-667 ccw(c-1251.09,-514.9) -1167.16,-652.38 ccw(c-1246.55,-522.18) -1140.12,-631.39 ccw(c-1243.58,-525.69) -1118.54,-604.7 ccw(c-1252.73,-519.85) -1103.42,-573.83 ccw(c-1256.81,-518.13) -1094.09,-505.87 ccw(c-1245.15,-517.4) -1100.62,-471.96 ccw(c-1244.98,-517.81) -1114.8,-440.38 ccw(c-1253.99,-523.08) -1135.61,-412.63 ccw(c-1255.53,-524.07) -1192.35,-373.05 ccw(c-1250.23,-512.03) -1225.86,-363.46 ccw(c-1250.62,-516.71) -1260.72,-361.81 ccw(c-1250.09,-526.22) -1295.21,-367.76 ccw(c-1249.67,-528.13) -1327.76,-380.84 ccw(c-1252.82,-522.42) -1356.78,-400.55 ccw(c-1259.19,-514.91) -1380.68,-426.34 ccw(c-1252.14,-519.84) -1398.11,-456.93 ccw(c-1244.52,-523.23) -1408.6,-490.65 ccw(c-1244.49,-523.36) -1411.81,-525.87 ccw(c-1252.46,-523.58) -1407.38,-560.97 ccw(c-1259.95,-525.2) -1395.05,-594.22 ccw(c-1250.32,-520.27) -1375.53,-623.89 ccw(c-1244.93,-515.95) -1350.07,-648.82 ccw(c-1245.98,-517.48) -1319.93,-667.86 ccw(c-1249.97,-525.78) -1286.35,-679.92 ccw(c-1250.64,-526.6) -1250.79,-684.02 ccw(c-1250.54,-517.34) -1215.13,-680.22 ccw(c-1250.81,-515.54) -1181.02,-668.9 ccw(c-1248.08,-521.3) -1150.13,-650.49 ccw(c-1246.12,-524.42) -1124.12,-625.54 ccw(c-1253.15,-518.48) -1104.19,-595.43 ccw(c-1254.9,-517.44) -1091.09,-561.71 ccw(c-1248.84,-518.98) -1085.55,-525.93 ccw(c-1244.72,-519.45) -1088.21,-489.75 ccw(c-1253.91,-521.12) -1098.78,-454.97 ccw(c-1256.02,-521.89) -1116.53,-423.17 ccw(c-1251.08,-518.26) -1140.73,-395.92 ccw(c-1247.79,-515.04) -1170.5,-374.76 ccw(c-1252.41,-523.28) -1204.26,-360.65 ccw(c-1253.23,-525.62) -1240.31,-354.02 ccw(c-1252.88,-519.62) -1276.98,-355.3 ccw(c-1253.36,-514.59) -1312.49,-364.81 ccw(c-1249.91,-523.49) -1345.09,-381.94 ccw(c-1248.51,-525.8) -1373.37,-405.66 ccw(c-1252.81,-521.8) -1395.9,-434.92 ccw(c-1257.38,-518.74) -1411.31,-468.56 ccw(c-1248.25,-521.78) -1418.94,-504.84 ccw(c-1247.78,-522.21) -1410.44,-578.23 ccw(c-1256.71,-524.68) -1394.25,-611.77 ccw(c-1248.49,-519.54) -1371,-640.96 ccw(c-1247.66,-519.23) -1308.62,-681.45 ccw(c-1251.54,-528.03) -1272.22,-690.41 ccw(c-1250.26,-518.38) -1234.68,-691.11 ccw(c-1250,-517.23) -1163.26,-668.7 ccw(c-1245.51,-526.11) -1132.95,-646.23 ccw(c-1252.15,-518.97) -1108.33,-617.56 ccw(c-1253.14,-517.86) -1079.9,-547.8 ccw(c-1243.11,-520.08) -1077.88,-509.88 ccw(c-1252.84,-520.66) -1084.32,-472.4 ccw(c-1254.63,-520.81) -1120.18,-405.6 ccw(c-1246.32,-514.29) -1148.28,-379.71 ccw(c-1252.05,-522.14) -1181.49,-360.66 ccw(c-1253.2,-523.91) -1256.29,-345.63 ccw(c-1252.96,-513.08) -1294.39,-350.8 ccw(c-1250.57,-522.44) -1330.45,-364.33 ccw(c-1249.77,-524.74) -1390.08,-412.7 ccw(c-1254.29,-519.94) -1423.15,-482.2 ccw(c-1246.91,-522.51) -1423.89,-559.45 ccw(c-1253.82,-523.05) -1391.23,-629.67 ccw(c-1246.87,-518.77) -1331.79,-679.79 ccw(c-1250.98,-524.77) -1256.4,-699.5 ccw(c-1249.84,-516.35) -1179.43,-685.56 ccw(c-1247.66,-523.64) -1115.8,-639.76 ccw(c-1253.69,-517.17) -1077.25,-571.14 ccw(c-1246.35,-520.19) -1071.94,-492.44 ccw(c-1255.5,-520.78) -1100.43,-418.55 ccw(c-1248.25,-516.83) -1158.03,-363.96 ccw(c-1253.78,-524.54) -1233.58,-338.67 ccw(c-1252.25,-512.64) -1273.72,-338.99 ccw(c-1251.06,-520.99) -1312.83,-348.31 ccw(c-1249.69,-525.58) -1380.88,-390.66 ccw(c-1257.93,-516.79) -1406.37,-421.98 ccw(c-1250.98,-521.01) -1424.24,-458.27 ccw(c-1246.23,-522.99) -1435.02,-538.18 ccw(c-1258.28,-523.76) -1427.1,-578.03 ccw(c-1250.92,-521.17) -1410.43,-615.14 ccw(c-1246.08,-518.59) -1355.4,-674.74 ccw(c-1253.15,-528.38) -1319.44,-694.15 ccw(c-1250.61,-521.37) -1279.98,-705.02 ccw(c-1249.42,-514.77) -1239.02,-707.18 ccw(c-1249.13,-517.7) -1198.5,-700.57 ccw(c-1246.42,-527.31) -1160.39,-685.15 ccw(c-1250.04,-521.23) -1126.67,-661.54 ccw(c-1254.53,-515.92) -1098.74,-631.17 ccw(c-1252.25,-517.45) -1077.89,-595.53 ccw(c-1243.07,-521.49) -1065.39,-556.11 ccw(c-1249.66,-520.51) -1062.07,-514.84 ccw(c-1256.86,-520.6) -1067.71,-473.72 ccw(c-1254.44,-519.86) -1081.97,-434.7 ccw(c-1245.44,-515.34) -1104.51,-399.75 ccw(c-1250.06,-519.54) -1134.36,-370.71 ccw(c-1254.72,-525.34) -1169.85,-348.72 ccw(c-1253.85,-523.2) -1209.23,-334.77 ccw(c-1251.6,-513.37) -1250.77,-329.81 ccw(c-1251.28,-519.16) -1292.41,-334.33 ccw(c-1249.73,-526.68) -1332.2,-347.75 ccw(c-1250.72,-524.84) -1368.26,-369.32 ccw(c-1256.87,-516.85) -1398.74,-398.33 ccw(c-1252.55,-519.97) -1421.93,-433.51 ccw(c-1245.56,-523.68) -1437.04,-472.94 ccw(c-1247.39,-523.34) -1443.43,-514.72 ccw(c-1257.44,-522.98) -1440.49,-556.93 ccw(c-1252.78,-521.71) -1428.11,-597.45 ccw(c-1245.24,-518.59) -1407.23,-634.44 ccw(c-1246.48,-519.65) -1378.94,-666.17 ccw(c-1253.14,-527.15) -1344.35,-690.96 ccw(c-1251.41,-523.18) -1305.01,-707.34 ccw(c-1248.94,-515.15) -1262.97,-714.86 ccw(c-1248.9,-516.55) -1220.24,-713.28 ccw(c-1247.37,-526.41) -1178.86,-702.37 ccw(c-1249.15,-523.05) -1140.95,-682.39 ccw(c-1253.9,-515.83) -1108.18,-654.63 ccw(c-1252.97,-516.53) -1082.01,-620.51 ccw(c-1244.45,-521.6) -1063.93,-581.45 ccw(c-1247.66,-521.02) -1055.11,-539.26 ccw(c-1256.48,-520.06) -1055.62,-496.08 ccw(c-1255.59,-519.81) -1065.3,-453.93 ccw(c-1246.33,-516.5) -1083.97,-414.89 ccw(c-1248.34,-518.31) -1111,-381.01 ccw(c-1254.87,-524.67) -1144.8,-353.73 ccw(c-1254.63,-524.02) -1183.65,-334.22 ccw(c-1251.31,-514.86) -1225.87,-323.65 ccw(c-1251.1,-517) -1269.45,-322.88 ccw(c-1250.34,-526.32) -1312.25,-331.58 ccw(c-1250.61,-525.96) -1352.27,-349.19 ccw(c-1255.51,-517.65) -1387.52,-375.12 ccw(c-1254.12,-518.41) -1416.05,-408.39 ccw(c-1246.26,-523.9) -1436.73,-447.13 ccw(c-1246.48,-523.97) -1448.73,-489.42 ccw(c-1255.9,-522.47) -1451.24,-533.36 ccw(c-1255.03,-521.91) -1443.76,-576.78 ccw(c-1245.56,-519.29) -1426.99,-617.63 ccw(c-1245.43,-519.38) -1401.91,-654.04 ccw(c-1252.5,-525.61) -1369.49,-684.14 ccw(c-1252.73,-525.07) -1331.05,-706.18 ccw(c-1248.63,-515.89) -1288.65,-719.36 ccw(c-1248.42,-515.6) -1244.37,-723.26 ccw(c-1248.13,-524.9) -1200.27,-717.43 ccw(c-1248.55,-525.32) -1158.56,-701.79 ccw(c-1253.11,-516.11) -1121.18,-677.39 ccw(c-1253.37,-515.56) -1089.79,-645.57 ccw(c-1246.11,-521.18) -1066.03,-607.68 ccw(c-1245.49,-522.04) -1051.41,-565.33 ccw(c-1255.72,-519.63) -1046.37,-520.74 ccw(c-1256.57,-519.48) -1050.9,-476.03 ccw(c-1247.74,-517.5) -1065.03,-433.34 ccw(c-1246.13,-517.3) -1088.47,-394.88 ccw(c-1254.68,-523.79) -1119.78,-362.4 ccw(c-1255.5,-524.54) -1157.33,-337.27 ccw(c-1251.47,-516.59) -1199.45,-320.85 ccw(c-1250.44,-514.63) -1244.26,-314.35 ccw(c-1250.9,-525.56) -1289.49,-317.8 ccw(c-1250.79,-526.94) -1333.02,-330.78 ccw(c-1254.3,-518.89) -1372.72,-352.89 ccw(c-1255.53,-516.35) -1406.48,-383.43 ccw(c-1247.24,-523.81) -1432.79,-420.68 ccw(c-1245.87,-524.74) -1450.61,-462.72 ccw(c-1254.17,-522.35) -1458.94,-507.65 ccw(c-1257.52,-521.66) -1456.92,-553.37 ccw(c-1246.3,-519.98) -1444.92,-597.61 ccw(c-1244.46,-519.43) -1423.77,-638.36 ccw(c-1251.46,-524.22) -1394.3,-673.59 ccw(c-1254.55,-526.81) -1357.6,-701.33 ccw(c-1248.6,-516.95) -1315.64,-720.38 ccw(c-1247.77,-514.91) -1270.52,-730.1 ccw(c-1248.52,-523.2) -1224.35,-729.86 ccw(c-1248.39,-527.84) -1179.35,-719.21 ccw(c-1252.26,-516.8) -1137.71,-698.91 ccw(c-1253.45,-514.63) -1101.27,-670.18 ccw(c-1247.65,-520.38) -1071.88,-634.27 ccw(c-1243.49,-523.54) -1051.28,-592.59 ccw(c-1254.6,-519.44) -1040.33,-547.33 ccw(c-1257.3,-518.94) -1039.24,-500.71 ccw(c-1249.35,-518.14) -1048.22,-454.92 ccw(c-1243.71,-516.76) -1067.3,-412.27 ccw(c-1254.06,-522.78) -1095.34,-374.79 ccw(c-1256.37,-524.73) -1130.76,-344.08 ccw(c-1252.02,-518.24) -1171.97,-321.7 ccw(c-1249.3,-512.46) -1217.23,-309.13 ccw(c-1251.26,-524.39) -1264.22,-306.85 ccw(c-1251.22,-527.7) -1310.7,-314.61 ccw(c-1253.4,-520.38) -1354.44,-332.19 ccw(c-1256.41,-514.12) -1393.17,-359.18 ccw(c-1248.4,-523.3) -1425.05,-394.11 ccw(c-1248.34,-523.95) -1463.22,-480.23 ccw(c-1259.74,-520.88) -1467.13,-527.52 ccw(c-1247.49,-520.55) -1460.5,-574.58 ccw(c-1246.57,-520.82) -1418.25,-659.31 ccw(c-1256.53,-527.95) -1384.14,-692.65 ccw(c-1248.95,-518.26) -1343.44,-717.65 ccw(c-1248,-517.36) -1250.76,-739.21 ccw(c-1248.82,-529.99) -1203.09,-734.16 ccw(c-1251.47,-517.97) -1157.65,-718.66 ccw(c-1251.74,-516.31) -1081.58,-660.69 ccw(c-1242.21,-525.22) -1054.95,-620.54 ccw(c-1253.16,-519.61) -1037.85,-575.43 ccw(c-1255,-518.67) -1034.02,-479.38 ccw(c-1241.7,-516.9) -1048.03,-433.03 ccw(c-1252.96,-521.76) -1072.02,-390.89 ccw(c-1255.18,-522.83) -1143.95,-326.4 ccw(c-1247.93,-511.14) -1188.82,-307.56 ccw(c-1251.32,-522.85) -1236.81,-299.14 ccw(c-1251.93,-525.65) -1332.83,-313.54 ccw(c-1253.77,-517.48) -1413.43,-367.97 ccw(c-1247.56,-524.84) -1463.77,-451.55 ccw(c-1255.46,-520.97) -1473.26,-548.83 ccw(c-1245.41,-520.81) -1440.78,-641.35 ccw(c-1253.77,-524.7) -1371.54,-711.01 ccw(c-1247.26,-516.49) -1279.1,-745.11 ccw(c-1249.59,-525.83) -1180.81,-736.13 ccw(c-1251.91,-515.2) -1095.19,-686.39 ccw(c-1245.87,-523.2) -1039.19,-604.54 ccw(c-1255.93,-518.08) -1022.88,-506.38 ccw(c-1245.52,-518.45) -1050.37,-410.6 ccw(c-1256.22,-523.14) -1115.93,-335.11 ccw(c-1246.9,-511.18) -1159.51,-309.89 ccw(c-1250.96,-520.99) -1207.69,-295.04 ccw(c-1252.37,-526.62) -1308.13,-297.46 ccw(c-1255.69,-511.77) -1355.57,-315.04 ccw(c-1250.85,-520.8) -1397.92,-342.83 ccw(c-1247.14,-525.79) -1460.37,-422.14 ccw(c-1260.73,-518.89) -1477.15,-470.13 ccw(c-1251.09,-520.8) -1482.76,-520.72 ccw(c-1244.44,-521.1) -1461.34,-619.86 ccw(c-1258.4,-527.2) -1434.94,-663.59 ccw(c-1251.15,-521.24) -1399.37,-700.33 ccw(c-1246.42,-515.96) -1308.89,-747.23 ccw(c-1250.59,-530.58) -1258.14,-754.81 ccw(c-1250.61,-521.67) -1206.91,-750.8 ccw(c-1252.05,-513.25) -1157.65,-735.87 ccw(c-1250.51,-516.46) -1112.66,-710.78 ccw(c-1243.16,-526.7) -1074.28,-676.35 ccw(c-1249.68,-521.39) -1044.58,-634.13 ccw(c-1257.35,-517) -1024.61,-586.42 ccw(c-1254.15,-517.78) -1015.22,-535.53 ccw(c-1241.54,-518.64) -1017.29,-483.77 ccw(c-1249.26,-520.23) -1030.95,-433.74 ccw(c-1257.79,-523.44) -1055.09,-387.73 ccw(c-1255.39,-521.63) -1088.48,-347.88 ccw(c-1246.69,-512.45) -1129.87,-316.32 ccw(c-1250.07,-518.94) -1177.34,-294.85 ccw(c-1253.12,-527.84) -1228.42,-284.09 ccw(c-1253.01,-525.11) -1280.66,-284.42 ccw(c-1254.55,-512.57) -1331.59,-296.24 ccw(c-1251.87,-518.74) -1378.61,-319.24 ccw(c-1246.8,-527.01) -1419.65,-351.9 ccw(c-1248.64,-525.39) -1452.84,-392.55 ccw(c-1259.26,-518.6) -1476.31,-439.54 ccw(c-1253.36,-520.24) -1488.61,-490.66 ccw(c-1243.47,-521.64) -1489.61,-543.34 ccw(c-1245.61,-522) -1479.39,-595.06 ccw(c-1257.55,-525.85) -1458.05,-643.33 ccw(c-1253.09,-522.64) -1426.36,-685.59 ccw(c-1245.5,-515.72) -1386.22,-720.08 ccw(c-1246.42,-517.35) -1339.63,-745.29 ccw(c-1251.04,-528.94) -1288.62,-759.69 ccw(c-1250.79,-524.11) -1235.61,-762.22 ccw(c-1251.31,-513.56) -1183.21,-753.23 ccw(c-1250.71,-515.03) -1133.87,-733.3 ccw(c-1244.76,-525.89) -1090.06,-703.04 ccw(c-1247.9,-523.15) -1054.15,-663.64 ccw(c-1256.59,-516.66) -1027.57,-617.32 ccw(c-1255.35,-517.01) -1011.4,-566.37 ccw(c-1243.29,-519.33) -1006.76,-513.08 ccw(c-1246.72,-520) -1014.27,-460.05 ccw(c-1257.53,-522.63) -1033.1,-409.82 ccw(c-1256.74,-522.03) -1062.2,-364.69 ccw(c-1247.36,-514.29) -1100.47,-326.97 ccw(c-1248.58,-516.81) -1146.31,-298.83 ccw(c-1253.56,-527.07) -1197.25,-281.25 ccw(c-1253.58,-526.37) -1250.81,-274.88 ccw(c-1253.58,-514.34) -1304.51,-280.34 ccw(c-1252.55,-516.18) -1355.65,-297.79 ccw(c-1247.7,-526.8) -1401.86,-325.98 ccw(c-1248.06,-526.63) -1441.09,-363.36 ccw(c-1257.22,-519.05) -1471.24,-408.41 ccw(c-1255.81,-519.08) -1490.48,-459.16 ccw(c-1244.26,-522.19) -1498.25,-512.97 ccw(c-1244.32,-522.37) -1494.43,-567.27 ccw(c-1255.84,-524.57) -1478.87,-619.45 ccw(c-1255.6,-523.79) -1451.91,-666.84 ccw(c-1245.63,-516.7) -1415.24,-707.3 ccw(c-1245.32,-516.63) -1370.76,-739.1 ccw(c-1250.88,-526.78) -1320.42,-760.48 ccw(c-1251.55,-526.81) -1266.49,-769.96 ccw(c-1250.63,-514.34) -1211.69,-767.47 ccw(c-1250.54,-513.74) -1158.61,-753.4 ccw(c-1246.32,-524.35) -1109.83,-728.13 ccw(c-1246.3,-525.51) -1067.96,-692.46 ccw(c-1255.52,-516.67) -1034.81,-648.46 ccw(c-1256.2,-516.06) -1011.72,-598.37 ccw(c-1245.5,-519.51) -1000.04,-544.44 ccw(c-1243.83,-520.29) -1000.83,-489.2 ccw(c-1256.77,-521.8) -1013.67,-435.38 ccw(c-1257.99,-522.04) -1037.66,-385.44 ccw(c-1248.66,-516.09) -1071.91,-341.88 ccw(c-1246.46,-514.76) -1115.16,-307.12 ccw(c-1253.68,-525.91) -1165.04,-282.6 ccw(c-1254.38,-527.3) -1219.04,-269.21 ccw(c-1253.05,-516.5) -1274.68,-267.82 ccw(c-1252.75,-513.21) -1329.27,-279.03 ccw(c-1248.68,-526.11) -1380.17,-301.94 ccw(c-1247.89,-527.82) -1425.11,-335.16 ccw(c-1255.24,-520.05) -1461.8,-377.33 ccw(c-1258.22,-517.3) -1488.09,-426.75 ccw(c-1245.47,-522.47) -1502.94,-480.8 ccw(c-1243.33,-523.01) -1505.98,-536.85 ccw(c-1253.8,-523.71) -1496.85,-592.24 ccw(c-1258.52,-524.48) -1475.44,-644.22 ccw(c-1246.24,-517.84) -1443.11,-690.31 ccw(c-1244.21,-516.32) -1401.68,-728.54 ccw(c-1250.22,-524.68) -1352.97,-756.93 ccw(c-1252.91,-529.49) -1299.05,-773.65 ccw(c-1250.16,-515.6) -1242.69,-778.13 ccw(c-1250.05,-512.73) -1186.59,-770.54 ccw(c-1247.49,-522.49) -1133.43,-751.02 ccw(c-1245.15,-528.27) -1085.97,-720 ccw(c-1254.22,-517.16) -1046.43,-679.26 ccw(c-1256.63,-515.04) -1016.4,-630.98 ccw(c-1247.66,-519.19) -997.47,-577.36 ccw(c-1241.02,-521.21) -991.08,-520.77 ccw(c-1255.51,-521.12) -997.3,-464.1 ccw(c-1259.01,-521.7) -1015.45,-409.96 ccw(c-1250.3,-517.53) -1044.82,-360.98 ccw(c-1243.97,-513.24) -1084.51,-319.81 ccw(c-1253.36,-524.46) -1132.35,-288.35 ccw(c-1255.29,-527.83) -1185.86,-267.75 ccw(c-1253.02,-518.67) -1242.56,-259.13 ccw(c-1252.29,-510.39) -1299.82,-263.47 ccw(c-1249.6,-524.87) -1354.78,-280.35 ccw(c-1248.1,-528.82) -1404.98,-308.58 ccw(c-1253.57,-521.43) -1447.94,-346.93 ccw(c-1260.01,-515.16) -1481.24,-394.01 ccw(c-1247.05,-522.36) -1503.35,-447.35 ccw(c-1246.47,-523.14) -1511.46,-562.04 ccw(c-1261.24,-524.43) -1496.36,-617.95 ccw(c-1247.39,-519) -1469.24,-669.2 ccw(c-1246.02,-518.77) -1385.68,-748.88 ccw(c-1254.67,-531.43) -1332.76,-772.99 ccw(c-1250.03,-517.28) -1275.75,-784.8 ccw(c-1249.31,-515.6) -1160.61,-771.14 ccw(c-1244.86,-530.76) -1108.08,-745.64 ccw(c-1252.82,-518.19) -1062.45,-709.09 ccw(c-1254.01,-516.22) -999.33,-611.25 ccw(c-1239.06,-522.58) -985.43,-554.29 ccw(c-1253.76,-520.72) -984.51,-495.59 ccw(c-1256.52,-520.44) -1019.82,-384.14 ccw(c-1241.77,-512.73) -1054.98,-336.92 ccw(c-1252.5,-522.82) -1099.8,-298.64 ccw(c-1254.73,-525.19) -1208.64,-254.63 ccw(c-1251.61,-515.58) -1325.98,-261.79 ccw(c-1249.75,-526.81) -1429.69,-317.83 ccw(c-1255.56,-517.93) -1499.25,-413.19 ccw(c-1245.24,-523.84) -1522.26,-529.3 ccw(c-1256.29,-522.74) -1493.02,-644.14 ccw(c-1244.71,-518.31) -1417.9,-736.24 ccw(c-1252.87,-526.56) -1310.35,-787.14 ccw(c-1248.81,-514.33) -1191.02,-787.95 ccw(c-1247.47,-526.34) -1082.81,-737.33 ccw(c-1254.63,-515.04) -1005.82,-645.52 ccw(c-1244.06,-521.82) -975.72,-529.42 ccw(c-1257.8,-520.14) -997.48,-411.1 ccw(c-1245.45,-516.07) -1068.03,-313.51 ccw(c-1255.78,-525.94) -1173.49,-254.64 ccw(c-1250.1,-508.44) -1233.34,-243.86 ccw(c-1250.63,-520.83) -1294.13,-246.75 ccw(c-1249.87,-528.06) -1407.16,-290.68 ccw(c-1259.78,-512.53) -1453.81,-330.06 ccw(c-1250.9,-520.47) -1490.48,-378.94 ccw(c-1244.4,-524.74) -1528.82,-494.49 ccw(c-1262.67,-522.5) -1528.21,-555.78 ccw(c-1251.42,-520.76) -1513.86,-615.43 ccw(c-1243.52,-518.27) -1449,-719.02 ccw(c-1256.83,-530.91) -1401.21,-757.78 ccw(c-1251.34,-521.59) -1345.9,-784.85 ccw(c-1247.76,-512.16) -1285.95,-799.45 ccw(c-1248.14,-516.55) -1224.25,-800.96 ccw(c-1246.79,-531.66) -1163.68,-788.81 ccw(c-1250.32,-522.08) -1107.34,-763.34 ccw(c-1255.48,-513.01) -1057.7,-726.3 ccw(c-1252.56,-515.86) -1017.05,-679.54 ccw(c-1240.02,-524.46) -987.68,-624.92 ccw(c-1249.07,-521.35) -971.33,-565.04 ccw(c-1259.68,-519.49) -968.22,-502.94 ccw(c-1255.96,-519.07) -978.39,-441.57 ccw(c-1241.33,-514.88) -1001.83,-383.9 ccw(c-1248.9,-519.58) -1037.68,-332.93 ccw(c-1257.35,-526.8) -1083.74,-290.8 ccw(c-1255.49,-523.93) -1137.72,-259.39 ccw(c-1249.41,-510) -1197.33,-240.62 ccw(c-1250.45,-518.15) -1259.69,-235.73 ccw(c-1250.26,-529.6) -1321.75,-244.4 ccw(c-1251.2,-526.67) -1380.58,-266.07 ccw(c-1258.05,-513.15) -1433.25,-300.16 ccw(c-1252.87,-518.56) -1476.94,-345.26 ccw(c-1243.66,-525.91) -1509.93,-398.82 ccw(c-1246.21,-524.92) -1530.81,-458.19 ccw(c-1260.92,-521.61) -1538.16,-520.74 ccw(c-1254.22,-521.03) -1531.23,-583.39 ccw(c-1242.35,-518.55) -1510.91,-643.18 ccw(c-1244.42,-519.73) -1478.34,-697.32 ccw(c-1256.28,-528.9) -1434.67,-743.03 ccw(c-1252.97,-523.95) -1381.77,-777.76 ccw(c-1247.18,-512.93) -1322.53,-800.29 ccw(c-1247.49,-514.94) -1259.81,-809.73 ccw(c-1247.97,-529.81) -1196.51,-805.21 ccw(c-1249.56,-524.9) -1135.8,-786.53 ccw(c-1254.49,-513.11) -1080.47,-755.11 ccw(c-1253.34,-514.34) -1033.04,-712.64 ccw(c-1242.29,-524.1) -996.03,-660.79 ccw(c-1246.37,-522.61) -971.63,-601.88 ccw(c-1258.92,-518.8) -960.54,-538.99 ccw(c-1257.6,-518.68) -963.05,-475.12 ccw(c-1243.18,-516.4) -979.45,-413.32 ccw(c-1246.14,-518.31) -1009.4,-356.76 ccw(c-1257.33,-525.74) -1050.96,-307.95 ccw(c-1256.84,-524.9) -1101.97,-269.03 ccw(c-1249.49,-512.48) -1160.26,-242.17 ccw(c-1249.62,-515.17) -1223.16,-229.13 ccw(c-1251.07,-528.84) -1287.51,-230.05 ccw(c-1251.35,-528.29) -1350.24,-244.61 ccw(c-1256.19,-514.89) -1408.31,-272.5 ccw(c-1254.65,-515.95) -1458.65,-312.81 ccw(c-1244.8,-526.01) -1499.1,-363.16 ccw(c-1245.1,-526.07) -1527.97,-421 ccw(c-1258.34,-521.33) -1543.56,-483.75 ccw(c-1257.41,-520.7) -1544.6,-548.48 ccw(c-1243.07,-519.49) -1531.52,-611.97 ccw(c-1242.85,-519.65) -1505.26,-671.3 ccw(c-1254.78,-526.73) -1466.71,-723.52 ccw(c-1255.32,-526.22) -1417.32,-765.74 ccw(c-1246.94,-514.14) -1359.84,-796.24 ccw(c-1246.54,-513.72) -1297.15,-813.88 ccw(c-1248.65,-527.22) -1232.1,-817.48 ccw(c-1249.34,-528.21) -1167.85,-806.3 ccw(c-1253.39,-513.76) -1107.49,-781.36 ccw(c-1253.64,-512.86) -1053.75,-744.15 ccw(c-1244.71,-522.93) -1009.34,-696.15 ccw(c-1243.66,-524.61) -976.87,-639.31 ccw(c-1257.66,-518.41) -957.55,-576.68 ccw(c-1258.89,-517.95) -951.95,-511.3 ccw(c-1245.65,-517.49) -960.66,-446.25 ccw(c-1242.82,-517.52) -983.83,-384.78 ccw(c-1256.78,-524.48) -1019.92,-329.77 ccw(c-1258.21,-525.38) -1066.9,-283.62 ccw(c-1250.27,-515.07) -1122.77,-248.73 ccw(c-1248.07,-512.09) -1185.14,-227.31 ccw(c-1251.66,-527.55) -1250.77,-220.03 ccw(c-1251.88,-529.62) -1316.52,-226.85 ccw(c-1254.72,-517.15) -1379.24,-247.73 ccw(c-1256.01,-512.75) -1435.71,-282.26 ccw(c-1246.21,-525.58) -1483.32,-328.36 ccw(c-1244.47,-527.32) -1520.1,-383.57 ccw(c-1255.67,-521.68) -1544.08,-445.44 ccw(c-1260.74,-519.66) -1553.52,-511.19 ccw(c-1244.36,-520.3) -1548.32,-577.5 ccw(c-1241.53,-519.99) -1529.14,-641.26 ccw(c-1252.8,-524.93) -1496.65,-699.39 ccw(c-1258.27,-528.08) -1451.85,-748.76 ccw(c-1247.2,-515.69) -1397.24,-787.15 ccw(c-1245.44,-512.97) -1335.65,-813.1 ccw(c-1248.73,-524.56) -1269.92,-825.17 ccw(c-1249.82,-531.65) -1203.08,-822.11 ccw(c-1252.35,-515.02) -1138.46,-804.44 ccw(c-1253.47,-511.56) -1079,-773.41 ccw(c-1246.78,-521.27) -1027.61,-730.29 ccw(c-1241.38,-527.19) -987.2,-676.66 ccw(c-1255.97,-518.45) -959.54,-615.38 ccw(c-1259.72,-516.99) -945.51,-549.55 ccw(c-1248.24,-517.99) -945.97,-482.23 ccw(c-1239.43,-517.47) -961.59,-416.67 ccw(c-1255.6,-523.2) -991.28,-356.08 ccw(c-1259.45,-525.37) -1033.22,-303.12 ccw(c-1251.56,-517.35) -1085.57,-260.42 ccw(c-1245.94,-509.53) -1146.25,-230.54 ccw(c-1251.86,-525.77) -1212.1,-214.75 ccw(c-1252.7,-530.51) -1279.89,-213.31 ccw(c-1253.83,-519.6) -1346.4,-226.48 ccw(c-1256.54,-509.55) -1408.32,-254.27 ccw(c-1247.75,-524.54) -1462.65,-295.09 ccw(c-1247.78,-525.53) -1539.48,-406.45 ccw(c-1263.43,-518.01) -1557.62,-472.11 ccw(c-1246.21,-520.79) -1560.8,-540.23 ccw(c-1244.91,-521.4) -1523.83,-670.87 ccw(c-1261.18,-528.99) -1484.67,-726.91 ccw(c-1248.06,-517.47) -1434.03,-772.94 ccw(c-1246.44,-516.39) -1309.35,-827.91 ccw(c-1251.01,-534.32) -1240.97,-833.48 ccw(c-1251.54,-516.88) -1172.99,-823.77 ccw(c-1251.51,-514.4) -1050.73,-762.52 ccw(c-1241.56,-528.25) -1002.65,-713.23 ccw(c-1254.25,-518.28) -966.57,-654.48 -940.56,-628.47 -936.28,-624.19 -920.19,-624.19 v2@-917.88,-621.88 ; v3@-1264.19,-498 v3(-1252,-498)
  other v1: -1252,-498
  other v2: -913,-624 -885,-624 -909,-560 -909,-532 -908,-440 -880,-440
  other v3: -1250,-545

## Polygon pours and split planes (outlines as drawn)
Net1 on Top Layer "NET1_L01_P002" (solid, pour order 2): -1600.98,-188.04 -604,-187 -558,-188.04 -557.83,-191 -558,-857 -1600.98,-857
Net1 on Bottom Layer "NET1_L04_P003" (solid, pour order 3): -1600.98,-188.04 -604,-187 -558,-188.04 -557.83,-191 -558,-857 -1600.98,-857

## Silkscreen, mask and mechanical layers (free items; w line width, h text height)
Top Overlay:
  lines w7.87: -788.43,-629.49 -788.43,-646.22 -749.06,-646.22 ; -788.43,-440.51 -788.43,-423.78 -749.06,-423.78 ; -621.1,-646.22 -591.57,-646.22 -591.57,-423.78 -621.1,-423.78
  text "TYP-A 4-LAYER 35-COILS" at -1068,-836 h31.5
Mechanical 2:
  the board outline again, w3.94
Mechanical 13:
  lines w3.94: -788.43,-646.22 -788.43,-423.78 -591.57,-423.78 -591.57,-646.22 -788.43,-646.22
